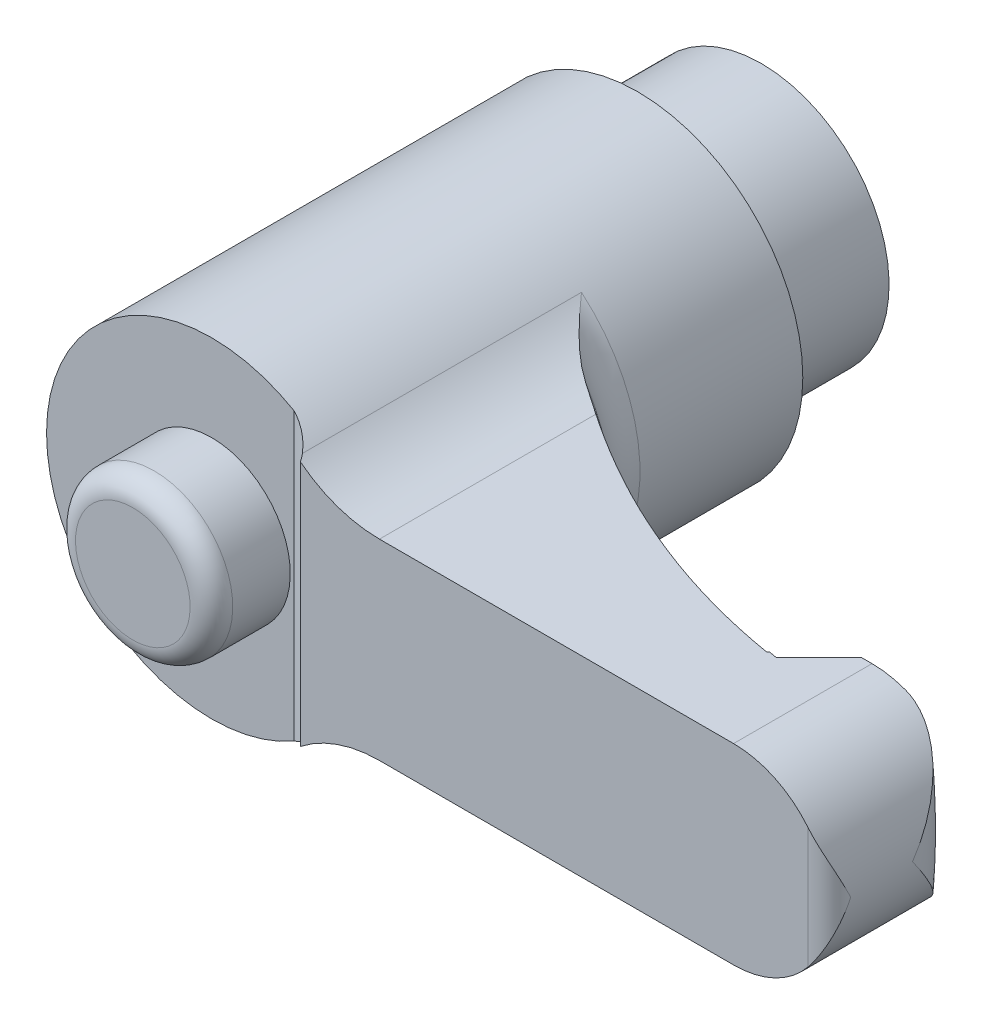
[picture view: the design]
ISO-10303-21;
HEADER;
FILE_DESCRIPTION(('STEP AP214'),'2;1');
FILE_NAME('part.step','',(''),(''),'','','');
FILE_SCHEMA(('AUTOMOTIVE_DESIGN { 1 0 10303 214 1 1 1 1 }'));
ENDSEC;
DATA;
#1=APPLICATION_CONTEXT('core data for automotive mechanical design processes');
#2=APPLICATION_PROTOCOL_DEFINITION('international standard','automotive_design',2000,#1);
#3=PRODUCT_CONTEXT('',#1,'mechanical');
#4=PRODUCT('Part','Part','',(#3));
#5=PRODUCT_RELATED_PRODUCT_CATEGORY('part','',(#4));
#6=PRODUCT_DEFINITION_FORMATION('','',#4);
#7=PRODUCT_DEFINITION_CONTEXT('part definition',#1,'design');
#8=PRODUCT_DEFINITION('design','',#6,#7);
#9=PRODUCT_DEFINITION_SHAPE('','',#8);
#10=(LENGTH_UNIT() NAMED_UNIT(*) SI_UNIT(.MILLI.,.METRE.));
#11=(NAMED_UNIT(*) PLANE_ANGLE_UNIT() SI_UNIT($,.RADIAN.));
#12=(NAMED_UNIT(*) SI_UNIT($,.STERADIAN.) SOLID_ANGLE_UNIT());
#13=UNCERTAINTY_MEASURE_WITH_UNIT(LENGTH_MEASURE(1.E-05),#10,'distance_accuracy_value','');
#14=(GEOMETRIC_REPRESENTATION_CONTEXT(3) GLOBAL_UNCERTAINTY_ASSIGNED_CONTEXT((#13)) GLOBAL_UNIT_ASSIGNED_CONTEXT((#10,
#11,#12)) REPRESENTATION_CONTEXT('',''));
#15=CARTESIAN_POINT('',(0.,0.,0.));
#16=DIRECTION('',(0.,0.,1.));
#17=DIRECTION('',(1.,0.,0.));
#18=AXIS2_PLACEMENT_3D('',#15,#16,#17);
#19=CARTESIAN_POINT('',(0.,0.,10.));
#20=DIRECTION('',(0.,0.,-1.));
#21=DIRECTION('',(-1.,0.,0.));
#22=AXIS2_PLACEMENT_3D('',#19,#20,#21);
#23=PLANE('',#22);
#24=CARTESIAN_POINT('',(0.,0.,10.));
#25=DIRECTION('',(0.,0.,-1.));
#26=DIRECTION('',(-1.,0.,0.));
#27=AXIS2_PLACEMENT_3D('',#24,#25,#26);
#28=CIRCLE('',#27,2.5);
#29=CARTESIAN_POINT('',(-2.5,0.,10.));
#30=VERTEX_POINT('',#29);
#31=EDGE_CURVE('E706',#30,#30,#28,.T.);
#32=ORIENTED_EDGE('',*,*,#31,.T.);
#33=EDGE_LOOP('',(#32));
#34=FACE_BOUND('',#33,.T.);
#35=ADVANCED_FACE('F14',(#34),#23,.T.);
#36=CARTESIAN_POINT('',(4.8,0.,0.));
#37=DIRECTION('',(0.,0.,1.));
#38=DIRECTION('',(0.,-1.,0.));
#39=AXIS2_PLACEMENT_3D('',#36,#37,#38);
#40=PLANE('',#39);
#41=CARTESIAN_POINT('',(0.,0.,0.));
#42=DIRECTION('',(0.,0.,-1.));
#43=DIRECTION('',(0.,1.,0.));
#44=AXIS2_PLACEMENT_3D('',#41,#42,#43);
#45=CIRCLE('',#44,2.5);
#46=CARTESIAN_POINT('',(0.,2.5,0.));
#47=VERTEX_POINT('',#46);
#48=EDGE_CURVE('E373',#47,#47,#45,.T.);
#49=ORIENTED_EDGE('',*,*,#48,.F.);
#50=EDGE_LOOP('',(#49));
#51=FACE_BOUND('',#50,.T.);
#52=CARTESIAN_POINT('',(0.,0.,0.));
#53=DIRECTION('',(0.,0.,-1.));
#54=DIRECTION('',(0.,1.,0.));
#55=AXIS2_PLACEMENT_3D('',#52,#53,#54);
#56=CIRCLE('',#55,4.8);
#57=CARTESIAN_POINT('',(0.,4.8,0.));
#58=VERTEX_POINT('',#57);
#59=EDGE_CURVE('E441',#58,#58,#56,.T.);
#60=ORIENTED_EDGE('',*,*,#59,.T.);
#61=EDGE_LOOP('',(#60));
#62=FACE_BOUND('',#61,.T.);
#63=ADVANCED_FACE('F334',(#51,#62),#40,.F.);
#64=CARTESIAN_POINT('',(0.,0.,26.));
#65=DIRECTION('',(0.,0.,-1.));
#66=DIRECTION('',(0.,1.,0.));
#67=AXIS2_PLACEMENT_3D('',#64,#65,#66);
#68=PLANE('',#67);
#69=CARTESIAN_POINT('',(0.,0.,26.));
#70=DIRECTION('',(0.,0.,-1.));
#71=DIRECTION('',(0.,1.,0.));
#72=AXIS2_PLACEMENT_3D('',#69,#70,#71);
#73=CIRCLE('',#72,7.75);
#74=CARTESIAN_POINT('',(3.875,-6.7116968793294,26.));
#75=VERTEX_POINT('',#74);
#76=CARTESIAN_POINT('',(3.875,6.7116968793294,26.));
#77=VERTEX_POINT('',#76);
#78=EDGE_CURVE('E426',#75,#77,#73,.T.);
#79=ORIENTED_EDGE('',*,*,#78,.F.);
#80=DIRECTION('',(0.,1.,0.));
#81=VECTOR('',#80,1.);
#82=CARTESIAN_POINT('',(3.875,-9.,26.));
#83=LINE('',#82,#81);
#84=EDGE_CURVE('E404',#75,#77,#83,.T.);
#85=ORIENTED_EDGE('',*,*,#84,.T.);
#86=EDGE_LOOP('',(#79,#85));
#87=FACE_BOUND('',#86,.T.);
#88=CARTESIAN_POINT('',(0.,0.,26.));
#89=DIRECTION('',(0.,0.,-1.));
#90=DIRECTION('',(0.,1.,0.));
#91=AXIS2_PLACEMENT_3D('',#88,#89,#90);
#92=CIRCLE('',#91,3.69047619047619);
#93=CARTESIAN_POINT('',(0.,3.69047619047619,26.));
#94=VERTEX_POINT('',#93);
#95=EDGE_CURVE('E9',#94,#94,#92,.F.);
#96=ORIENTED_EDGE('',*,*,#95,.F.);
#97=EDGE_LOOP('',(#96));
#98=FACE_BOUND('',#97,.T.);
#99=ADVANCED_FACE('F16',(#87,#98),#68,.F.);
#100=CARTESIAN_POINT('',(25.5,0.,0.));
#101=DIRECTION('',(0.,0.,1.));
#102=DIRECTION('',(0.,-1.,0.));
#103=AXIS2_PLACEMENT_3D('',#100,#101,#102);
#104=CYLINDRICAL_SURFACE('',#103,4.5);
#105=CARTESIAN_POINT('',(30.,0.,23.1));
#106=CARTESIAN_POINT('',(30.0000000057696,-0.00397224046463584,23.0972162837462));
#107=CARTESIAN_POINT('',(29.9999947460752,-0.00794462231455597,23.0944324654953));
#108=CARTESIAN_POINT('',(29.9991779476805,-0.316207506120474,22.8784039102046));
#109=CARTESIAN_POINT('',(29.967472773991,-0.621260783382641,22.6646232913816));
#110=CARTESIAN_POINT('',(29.8729566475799,-1.07288244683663,22.3499400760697));
#111=CARTESIAN_POINT('',(29.8335087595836,-1.2227001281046,22.2458576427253));
#112=CARTESIAN_POINT('',(29.7386099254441,-1.51933949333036,22.0407893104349));
#113=CARTESIAN_POINT('',(29.6831664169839,-1.6661625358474,21.9398019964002));
#114=CARTESIAN_POINT('',(29.5225221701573,-2.0316181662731,21.690355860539));
#115=CARTESIAN_POINT('',(29.4064726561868,-2.24755940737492,21.5447545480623));
#116=CARTESIAN_POINT('',(29.1349908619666,-2.66429651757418,21.2699985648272));
#117=CARTESIAN_POINT('',(28.9796468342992,-2.86512503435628,21.1408080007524));
#118=CARTESIAN_POINT('',(28.6740094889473,-3.19567948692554,20.9378778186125));
#119=CARTESIAN_POINT('',(28.5328529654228,-3.3303385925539,20.8584463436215));
#120=CARTESIAN_POINT('',(28.2285136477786,-3.58389708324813,20.7186599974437));
#121=CARTESIAN_POINT('',(28.0653563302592,-3.70281438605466,20.6582833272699));
#122=CARTESIAN_POINT('',(27.7569268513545,-3.89637158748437,20.5739705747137));
#123=CARTESIAN_POINT('',(27.6155988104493,-3.97499958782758,20.5449430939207));
#124=CARTESIAN_POINT('',(27.3962983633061,-4.08175109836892,20.516319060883));
#125=CARTESIAN_POINT('',(27.3219652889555,-4.11547521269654,20.5092639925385));
#126=CARTESIAN_POINT('',(27.1713145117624,-4.17892025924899,20.5006475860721));
#127=CARTESIAN_POINT('',(27.0949977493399,-4.20864304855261,20.4990836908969));
#128=CARTESIAN_POINT('',(26.940135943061,-4.26413478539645,20.5019689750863));
#129=CARTESIAN_POINT('',(26.8615759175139,-4.28985895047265,20.5064814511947));
#130=CARTESIAN_POINT('',(26.7037978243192,-4.33677756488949,20.5220962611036));
#131=CARTESIAN_POINT('',(26.624580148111,-4.35797453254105,20.5331949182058));
#132=CARTESIAN_POINT('',(26.4663684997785,-4.39576374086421,20.5623470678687));
#133=CARTESIAN_POINT('',(26.3873744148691,-4.41235899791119,20.5803959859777));
#134=CARTESIAN_POINT('',(26.230581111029,-4.44101436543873,20.6236628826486));
#135=CARTESIAN_POINT('',(26.1527814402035,-4.4530762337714,20.6488780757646));
#136=CARTESIAN_POINT('',(25.9747863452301,-4.47604389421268,20.7158088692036));
#137=CARTESIAN_POINT('',(25.8753706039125,-4.48535121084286,20.7602222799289));
#138=CARTESIAN_POINT('',(25.7308199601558,-4.4943380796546,20.836059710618));
#139=CARTESIAN_POINT('',(25.6833620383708,-4.49650441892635,20.8629005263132));
#140=CARTESIAN_POINT('',(25.5902043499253,-4.4993369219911,20.9195771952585));
#141=CARTESIAN_POINT('',(25.5445050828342,-4.50000266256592,20.9494138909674));
#142=CARTESIAN_POINT('',(25.4998,-4.49999999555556,20.980704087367));
#143=B_SPLINE_CURVE_WITH_KNOTS('',3,(#105,#106,#107,#108,#109,#110,#111,#112,#113,#114,#115,
#116,#117,#118,#119,#120,#121,#122,#123,#124,#125,#126,#127,#128,#129,#130,#131,#132,#133,#134,
#135,#136,#137,#138,#139,#140,#141,#142),.UNSPECIFIED.,.F.,.F.,(4,2,2,2,2,2,2,2,2,2,2,2,2,2,2,2,
2,2,4),(0.,0.0145521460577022,1.12923174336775,1.68863416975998,2.24777690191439,
3.0999476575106,3.95022123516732,4.58000022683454,5.20905610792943,5.69992949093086,
5.94545977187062,6.19087570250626,6.43886797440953,6.68672193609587,6.93441304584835,
7.18200801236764,7.50864895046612,7.67223429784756,7.83586577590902),.UNSPECIFIED.);
#144=CARTESIAN_POINT('',(27.0737254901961,-4.21584962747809,20.5));
#145=VERTEX_POINT('',#144);
#146=CARTESIAN_POINT('',(30.,0.,23.1));
#147=VERTEX_POINT('',#146);
#148=EDGE_CURVE('E133',#145,#147,#143,.F.);
#149=ORIENTED_EDGE('',*,*,#148,.T.);
#150=CARTESIAN_POINT('',(30.,0.,23.1));
#151=CARTESIAN_POINT('',(30.0000000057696,0.00397224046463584,23.0972162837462));
#152=CARTESIAN_POINT('',(29.9999947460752,0.00794462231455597,23.0944324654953));
#153=CARTESIAN_POINT('',(29.9991779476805,0.316207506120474,22.8784039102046));
#154=CARTESIAN_POINT('',(29.967472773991,0.621260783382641,22.6646232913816));
#155=CARTESIAN_POINT('',(29.8729566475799,1.07288244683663,22.3499400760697));
#156=CARTESIAN_POINT('',(29.8335087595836,1.2227001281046,22.2458576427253));
#157=CARTESIAN_POINT('',(29.7386099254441,1.51933949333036,22.0407893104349));
#158=CARTESIAN_POINT('',(29.6831664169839,1.6661625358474,21.9398019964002));
#159=CARTESIAN_POINT('',(29.5225221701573,2.0316181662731,21.690355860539));
#160=CARTESIAN_POINT('',(29.4064726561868,2.24755940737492,21.5447545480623));
#161=CARTESIAN_POINT('',(29.1349908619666,2.66429651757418,21.2699985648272));
#162=CARTESIAN_POINT('',(28.9796468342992,2.86512503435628,21.1408080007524));
#163=CARTESIAN_POINT('',(28.6740094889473,3.19567948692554,20.9378778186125));
#164=CARTESIAN_POINT('',(28.5328529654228,3.3303385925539,20.8584463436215));
#165=CARTESIAN_POINT('',(28.2285136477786,3.58389708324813,20.7186599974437));
#166=CARTESIAN_POINT('',(28.0653563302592,3.70281438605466,20.6582833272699));
#167=CARTESIAN_POINT('',(27.7569268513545,3.89637158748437,20.5739705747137));
#168=CARTESIAN_POINT('',(27.6155988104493,3.97499958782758,20.5449430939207));
#169=CARTESIAN_POINT('',(27.3962983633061,4.08175109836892,20.516319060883));
#170=CARTESIAN_POINT('',(27.3219652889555,4.11547521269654,20.5092639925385));
#171=CARTESIAN_POINT('',(27.1713145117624,4.17892025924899,20.5006475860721));
#172=CARTESIAN_POINT('',(27.0949977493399,4.20864304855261,20.4990836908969));
#173=CARTESIAN_POINT('',(26.940135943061,4.26413478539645,20.5019689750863));
#174=CARTESIAN_POINT('',(26.8615759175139,4.28985895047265,20.5064814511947));
#175=CARTESIAN_POINT('',(26.7037978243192,4.33677756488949,20.5220962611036));
#176=CARTESIAN_POINT('',(26.624580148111,4.35797453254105,20.5331949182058));
#177=CARTESIAN_POINT('',(26.4663684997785,4.39576374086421,20.5623470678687));
#178=CARTESIAN_POINT('',(26.3873744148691,4.41235899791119,20.5803959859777));
#179=CARTESIAN_POINT('',(26.230581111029,4.44101436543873,20.6236628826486));
#180=CARTESIAN_POINT('',(26.1527814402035,4.4530762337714,20.6488780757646));
#181=CARTESIAN_POINT('',(25.9747863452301,4.47604389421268,20.7158088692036));
#182=CARTESIAN_POINT('',(25.8753706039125,4.48535121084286,20.7602222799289));
#183=CARTESIAN_POINT('',(25.7308199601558,4.4943380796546,20.836059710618));
#184=CARTESIAN_POINT('',(25.6833620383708,4.49650441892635,20.8629005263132));
#185=CARTESIAN_POINT('',(25.5902043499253,4.4993369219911,20.9195771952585));
#186=CARTESIAN_POINT('',(25.5445050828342,4.50000266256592,20.9494138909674));
#187=CARTESIAN_POINT('',(25.4998,4.49999999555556,20.980704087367));
#188=B_SPLINE_CURVE_WITH_KNOTS('',3,(#150,#151,#152,#153,#154,#155,#156,#157,#158,#159,#160,
#161,#162,#163,#164,#165,#166,#167,#168,#169,#170,#171,#172,#173,#174,#175,#176,#177,#178,#179,
#180,#181,#182,#183,#184,#185,#186,#187),.UNSPECIFIED.,.F.,.F.,(4,2,2,2,2,2,2,2,2,2,2,2,2,2,2,2,
2,2,4),(0.,0.0145521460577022,1.12923174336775,1.68863416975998,2.24777690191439,
3.0999476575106,3.95022123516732,4.58000022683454,5.20905610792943,5.69992949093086,
5.94545977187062,6.19087570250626,6.43886797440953,6.68672193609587,6.93441304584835,
7.18200801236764,7.50864895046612,7.67223429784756,7.83586577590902),.UNSPECIFIED.);
#189=CARTESIAN_POINT('',(27.0737254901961,4.21584962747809,20.5));
#190=VERTEX_POINT('',#189);
#191=EDGE_CURVE('E130',#147,#190,#188,.T.);
#192=ORIENTED_EDGE('',*,*,#191,.T.);
#193=CARTESIAN_POINT('',(25.5,0.,20.5));
#194=DIRECTION('',(0.,0.,-1.));
#195=DIRECTION('',(0.,1.,0.));
#196=AXIS2_PLACEMENT_3D('',#193,#194,#195);
#197=CIRCLE('',#196,4.5);
#198=CARTESIAN_POINT('',(25.5,4.5,20.5));
#199=VERTEX_POINT('',#198);
#200=EDGE_CURVE('E469',#190,#199,#197,.F.);
#201=ORIENTED_EDGE('',*,*,#200,.T.);
#202=DIRECTION('',(0.,0.,1.));
#203=VECTOR('',#202,1.);
#204=CARTESIAN_POINT('',(25.5,4.5,0.));
#205=LINE('',#204,#203);
#206=CARTESIAN_POINT('',(25.5,4.5,27.));
#207=VERTEX_POINT('',#206);
#208=EDGE_CURVE('E448',#199,#207,#205,.T.);
#209=ORIENTED_EDGE('',*,*,#208,.T.);
#210=CARTESIAN_POINT('',(25.5,0.,27.));
#211=DIRECTION('',(0.,0.,1.));
#212=DIRECTION('',(0.,-1.,0.));
#213=AXIS2_PLACEMENT_3D('',#210,#211,#212);
#214=CIRCLE('',#213,4.5);
#215=CARTESIAN_POINT('',(29.,2.82842712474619,27.));
#216=VERTEX_POINT('',#215);
#217=EDGE_CURVE('E422',#216,#207,#214,.T.);
#218=ORIENTED_EDGE('',*,*,#217,.F.);
#219=CARTESIAN_POINT('',(29.,2.82842712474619,27.));
#220=CARTESIAN_POINT('',(29.0452569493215,2.77244060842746,26.9999705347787));
#221=CARTESIAN_POINT('',(29.08910814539,2.71541373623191,26.9969310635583));
#222=CARTESIAN_POINT('',(29.1737346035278,2.59976408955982,26.9857221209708));
#223=CARTESIAN_POINT('',(29.2145155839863,2.54114457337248,26.9775624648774));
#224=CARTESIAN_POINT('',(29.2926216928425,2.42301598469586,26.9570723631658));
#225=CARTESIAN_POINT('',(29.3299701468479,2.36351669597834,26.9447732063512));
#226=CARTESIAN_POINT('',(29.4015263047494,2.24343051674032,26.9166544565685));
#227=CARTESIAN_POINT('',(29.4357319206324,2.18284293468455,26.9008325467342));
#228=CARTESIAN_POINT('',(29.5205149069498,2.0242761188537,26.8558925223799));
#229=CARTESIAN_POINT('',(29.5686353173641,1.92562477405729,26.8244847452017));
#230=CARTESIAN_POINT('',(29.6569408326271,1.7267576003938,26.7560098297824));
#231=CARTESIAN_POINT('',(29.6971228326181,1.62654117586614,26.7189404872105));
#232=CARTESIAN_POINT('',(29.769924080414,1.42454335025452,26.6403878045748));
#233=CARTESIAN_POINT('',(29.8025090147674,1.32275698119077,26.5988856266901));
#234=CARTESIAN_POINT('',(29.8600923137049,1.1184186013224,26.5127603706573));
#235=CARTESIAN_POINT('',(29.8850925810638,1.0158667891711,26.4681380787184));
#236=CARTESIAN_POINT('',(29.9373931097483,0.763467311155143,26.3559210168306));
#237=CARTESIAN_POINT('',(29.9605764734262,0.613303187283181,26.2871011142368));
#238=CARTESIAN_POINT('',(29.9916507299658,0.312779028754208,26.1474204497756));
#239=CARTESIAN_POINT('',(29.999578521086,0.162420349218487,26.0765650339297));
#240=CARTESIAN_POINT('',(29.9999945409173,0.00809034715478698,26.0038138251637));
#241=CARTESIAN_POINT('',(29.999999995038,0.00404514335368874,26.0019068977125));
#242=CARTESIAN_POINT('',(30.,0.,26.));
#243=B_SPLINE_CURVE_WITH_KNOTS('',3,(#219,#220,#221,#222,#223,#224,#225,#226,#227,#228,#229,
#230,#231,#232,#233,#234,#235,#236,#237,#238,#239,#240,#241,#242),.UNSPECIFIED.,.F.,.F.,(4,2,2,
2,2,2,2,2,2,2,2,4),(0.,0.215782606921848,0.431152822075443,0.644930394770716,0.858848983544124,
1.20082332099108,1.5429311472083,1.88655545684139,2.23009348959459,2.7297347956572,
3.22816610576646,3.2415825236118),.UNSPECIFIED.);
#244=CARTESIAN_POINT('',(30.,0.,26.));
#245=VERTEX_POINT('',#244);
#246=EDGE_CURVE('E173',#245,#216,#243,.F.);
#247=ORIENTED_EDGE('',*,*,#246,.F.);
#248=CARTESIAN_POINT('',(29.,-2.82842712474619,27.));
#249=CARTESIAN_POINT('',(29.0452569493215,-2.77244060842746,26.9999705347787));
#250=CARTESIAN_POINT('',(29.08910814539,-2.71541373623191,26.9969310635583));
#251=CARTESIAN_POINT('',(29.1737346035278,-2.59976408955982,26.9857221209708));
#252=CARTESIAN_POINT('',(29.2145155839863,-2.54114457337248,26.9775624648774));
#253=CARTESIAN_POINT('',(29.2926216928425,-2.42301598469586,26.9570723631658));
#254=CARTESIAN_POINT('',(29.3299701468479,-2.36351669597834,26.9447732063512));
#255=CARTESIAN_POINT('',(29.4015263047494,-2.24343051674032,26.9166544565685));
#256=CARTESIAN_POINT('',(29.4357319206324,-2.18284293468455,26.9008325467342));
#257=CARTESIAN_POINT('',(29.5205149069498,-2.0242761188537,26.8558925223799));
#258=CARTESIAN_POINT('',(29.5686353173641,-1.92562477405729,26.8244847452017));
#259=CARTESIAN_POINT('',(29.6569408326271,-1.7267576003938,26.7560098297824));
#260=CARTESIAN_POINT('',(29.6971228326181,-1.62654117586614,26.7189404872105));
#261=CARTESIAN_POINT('',(29.769924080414,-1.42454335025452,26.6403878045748));
#262=CARTESIAN_POINT('',(29.8025090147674,-1.32275698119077,26.5988856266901));
#263=CARTESIAN_POINT('',(29.8600923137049,-1.1184186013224,26.5127603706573));
#264=CARTESIAN_POINT('',(29.8850925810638,-1.0158667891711,26.4681380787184));
#265=CARTESIAN_POINT('',(29.9373931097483,-0.763467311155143,26.3559210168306));
#266=CARTESIAN_POINT('',(29.9605764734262,-0.613303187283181,26.2871011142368));
#267=CARTESIAN_POINT('',(29.9916507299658,-0.312779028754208,26.1474204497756));
#268=CARTESIAN_POINT('',(29.999578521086,-0.162420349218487,26.0765650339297));
#269=CARTESIAN_POINT('',(29.9999945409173,-0.00809034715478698,26.0038138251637));
#270=CARTESIAN_POINT('',(29.999999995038,-0.00404514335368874,26.0019068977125));
#271=CARTESIAN_POINT('',(30.,0.,26.));
#272=B_SPLINE_CURVE_WITH_KNOTS('',3,(#248,#249,#250,#251,#252,#253,#254,#255,#256,#257,#258,
#259,#260,#261,#262,#263,#264,#265,#266,#267,#268,#269,#270,#271),.UNSPECIFIED.,.F.,.F.,(4,2,2,
2,2,2,2,2,2,2,2,4),(0.,0.215782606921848,0.431152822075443,0.644930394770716,0.858848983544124,
1.20082332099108,1.5429311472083,1.88655545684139,2.23009348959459,2.7297347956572,
3.22816610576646,3.2415825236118),.UNSPECIFIED.);
#273=CARTESIAN_POINT('',(29.,-2.82842712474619,27.));
#274=VERTEX_POINT('',#273);
#275=EDGE_CURVE('E22',#274,#245,#272,.T.);
#276=ORIENTED_EDGE('',*,*,#275,.F.);
#277=CARTESIAN_POINT('',(25.5,-4.5,27.));
#278=VERTEX_POINT('',#277);
#279=EDGE_CURVE('E419',#278,#274,#214,.T.);
#280=ORIENTED_EDGE('',*,*,#279,.F.);
#281=DIRECTION('',(0.,0.,1.));
#282=VECTOR('',#281,1.);
#283=CARTESIAN_POINT('',(25.5,-4.5,0.));
#284=LINE('',#283,#282);
#285=CARTESIAN_POINT('',(25.5,-4.5,20.5));
#286=VERTEX_POINT('',#285);
#287=EDGE_CURVE('E451',#286,#278,#284,.T.);
#288=ORIENTED_EDGE('',*,*,#287,.F.);
#289=EDGE_CURVE('E140',#286,#145,#197,.F.);
#290=ORIENTED_EDGE('',*,*,#289,.T.);
#291=EDGE_LOOP('',(#149,#192,#201,#209,#218,#247,#276,#280,#288,#290));
#292=FACE_BOUND('',#291,.T.);
#293=ADVANCED_FACE('F138',(#292),#104,.T.);
#294=CARTESIAN_POINT('',(28.072410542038,-9.,-7.06806810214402));
#295=DIRECTION('',(0.,1.,0.));
#296=DIRECTION('',(-1.,0.,0.));
#297=AXIS2_PLACEMENT_3D('',#294,#295,#296);
#298=CYLINDRICAL_SURFACE('',#297,30.);
#299=CARTESIAN_POINT('',(22.457864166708,5.40076351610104,22.4018635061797));
#300=CARTESIAN_POINT('',(22.5328704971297,5.02783315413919,22.4161416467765));
#301=CARTESIAN_POINT('',(22.6003478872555,4.65331694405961,22.4287120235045));
#302=CARTESIAN_POINT('',(22.7199001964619,3.90172149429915,22.4506465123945));
#303=CARTESIAN_POINT('',(22.7719742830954,3.52464211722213,22.4600104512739));
#304=CARTESIAN_POINT('',(22.860391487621,2.76836181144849,22.4757441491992));
#305=CARTESIAN_POINT('',(22.8967259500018,2.38915983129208,22.4821122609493));
#306=CARTESIAN_POINT('',(22.953399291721,1.62955869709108,22.4919810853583));
#307=CARTESIAN_POINT('',(22.9737386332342,1.24915957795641,22.4954818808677));
#308=CARTESIAN_POINT('',(23.0101209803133,0.119914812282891,22.5017516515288));
#309=CARTESIAN_POINT('',(23.0030278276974,-0.62982701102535,22.5005458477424));
#310=CARTESIAN_POINT('',(22.9265280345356,-2.12549757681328,22.487326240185));
#311=CARTESIAN_POINT('',(22.8571649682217,-2.87142861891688,22.4753199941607));
#312=CARTESIAN_POINT('',(22.717445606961,-3.91200869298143,22.450161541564));
#313=CARTESIAN_POINT('',(22.6723784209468,-4.21035002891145,22.4419679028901));
#314=CARTESIAN_POINT('',(22.5724363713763,-4.80637536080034,22.4235048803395));
#315=CARTESIAN_POINT('',(22.5175283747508,-5.10405358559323,22.4132284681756));
#316=CARTESIAN_POINT('',(22.457864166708,-5.40076351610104,22.4018635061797));
#317=B_SPLINE_CURVE_WITH_KNOTS('',3,(#299,#300,#301,#302,#303,#304,#305,#306,#307,#308,#309,
#310,#311,#312,#313,#314,#315,#316),.UNSPECIFIED.,.F.,.F.,(4,2,2,2,2,2,2,2,4),(0.,
1.14192528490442,2.28391227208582,3.4265264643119,4.56910763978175,6.81558260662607,
9.06048679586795,9.96586555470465,10.8743519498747),.UNSPECIFIED.);
#318=CARTESIAN_POINT('',(23.,0.,22.5));
#319=VERTEX_POINT('',#318);
#320=CARTESIAN_POINT('',(22.6238084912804,-4.5,22.4329951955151));
#321=VERTEX_POINT('',#320);
#322=EDGE_CURVE('E136',#319,#321,#317,.T.);
#323=ORIENTED_EDGE('',*,*,#322,.F.);
#324=DIRECTION('',(0.,1.,0.));
#325=VECTOR('',#324,1.);
#326=CARTESIAN_POINT('',(23.,-9.,22.5));
#327=LINE('',#326,#325);
#328=CARTESIAN_POINT('',(23.,-4.5,22.5));
#329=VERTEX_POINT('',#328);
#330=EDGE_CURVE('E386',#329,#319,#327,.T.);
#331=ORIENTED_EDGE('',*,*,#330,.F.);
#332=CARTESIAN_POINT('',(28.072410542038,-4.5,-7.06806810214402));
#333=DIRECTION('',(0.,1.,0.));
#334=DIRECTION('',(-1.,0.,0.));
#335=AXIS2_PLACEMENT_3D('',#332,#333,#334);
#336=CIRCLE('',#335,30.);
#337=EDGE_CURVE('E388',#329,#321,#336,.F.);
#338=ORIENTED_EDGE('',*,*,#337,.T.);
#339=EDGE_LOOP('',(#323,#331,#338));
#340=FACE_BOUND('',#339,.T.);
#341=ADVANCED_FACE('F162',(#340),#298,.F.);
#342=CARTESIAN_POINT('',(27.4,-9.,20.5));
#343=DIRECTION('',(0.,0.,-1.));
#344=DIRECTION('',(0.,1.,0.));
#345=AXIS2_PLACEMENT_3D('',#342,#343,#344);
#346=PLANE('',#345);
#347=ORIENTED_EDGE('',*,*,#200,.F.);
#348=CARTESIAN_POINT('',(0.,0.,20.5));
#349=DIRECTION('',(0.,0.,-1.));
#350=DIRECTION('',(0.,1.,0.));
#351=AXIS2_PLACEMENT_3D('',#348,#349,#350);
#352=CIRCLE('',#351,27.4);
#353=EDGE_CURVE('E37',#190,#145,#352,.T.);
#354=ORIENTED_EDGE('',*,*,#353,.T.);
#355=ORIENTED_EDGE('',*,*,#289,.F.);
#356=DIRECTION('',(-1.,0.,0.));
#357=VECTOR('',#356,1.);
#358=CARTESIAN_POINT('',(25.5,-4.5,20.5));
#359=LINE('',#358,#357);
#360=CARTESIAN_POINT('',(25.,-4.5,20.5));
#361=VERTEX_POINT('',#360);
#362=EDGE_CURVE('E420',#286,#361,#359,.T.);
#363=ORIENTED_EDGE('',*,*,#362,.T.);
#364=DIRECTION('',(0.,1.,0.));
#365=VECTOR('',#364,1.);
#366=CARTESIAN_POINT('',(25.,-9.,20.5));
#367=LINE('',#366,#365);
#368=CARTESIAN_POINT('',(25.,4.5,20.5));
#369=VERTEX_POINT('',#368);
#370=EDGE_CURVE('E396',#361,#369,#367,.T.);
#371=ORIENTED_EDGE('',*,*,#370,.T.);
#372=DIRECTION('',(1.,0.,0.));
#373=VECTOR('',#372,1.);
#374=CARTESIAN_POINT('',(8.87764045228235,4.5,20.5));
#375=LINE('',#374,#373);
#376=EDGE_CURVE('E466',#369,#199,#375,.T.);
#377=ORIENTED_EDGE('',*,*,#376,.T.);
#378=EDGE_LOOP('',(#347,#354,#355,#363,#371,#377));
#379=FACE_BOUND('',#378,.T.);
#380=ADVANCED_FACE('F191',(#379),#346,.T.);
#381=CARTESIAN_POINT('',(0.,0.,27.));
#382=DIRECTION('',(0.,0.,1.));
#383=DIRECTION('',(0.,-1.,0.));
#384=AXIS2_PLACEMENT_3D('',#381,#382,#383);
#385=PLANE('',#384);
#386=CARTESIAN_POINT('',(8.87764045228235,10.5,27.));
#387=DIRECTION('',(0.,0.,1.));
#388=DIRECTION('',(1.,0.,0.));
#389=AXIS2_PLACEMENT_3D('',#386,#387,#388);
#390=CIRCLE('',#389,6.);
#391=CARTESIAN_POINT('',(5.16666666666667,5.78527057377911,27.));
#392=VERTEX_POINT('',#391);
#393=CARTESIAN_POINT('',(8.87764045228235,4.5,27.));
#394=VERTEX_POINT('',#393);
#395=EDGE_CURVE('E463',#392,#394,#390,.T.);
#396=ORIENTED_EDGE('',*,*,#395,.F.);
#397=DIRECTION('',(0.,1.,0.));
#398=VECTOR('',#397,1.);
#399=CARTESIAN_POINT('',(5.16666666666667,-9.,27.));
#400=LINE('',#399,#398);
#401=CARTESIAN_POINT('',(5.16666666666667,-5.78527057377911,27.));
#402=VERTEX_POINT('',#401);
#403=EDGE_CURVE('E402',#402,#392,#400,.T.);
#404=ORIENTED_EDGE('',*,*,#403,.F.);
#405=CARTESIAN_POINT('',(8.87764045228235,-10.5,27.));
#406=DIRECTION('',(0.,0.,1.));
#407=DIRECTION('',(1.,0.,0.));
#408=AXIS2_PLACEMENT_3D('',#405,#406,#407);
#409=CIRCLE('',#408,6.);
#410=CARTESIAN_POINT('',(8.87764045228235,-4.5,27.));
#411=VERTEX_POINT('',#410);
#412=EDGE_CURVE('E418',#411,#402,#409,.T.);
#413=ORIENTED_EDGE('',*,*,#412,.F.);
#414=DIRECTION('',(-1.,0.,0.));
#415=VECTOR('',#414,1.);
#416=CARTESIAN_POINT('',(25.5,-4.5,27.));
#417=LINE('',#416,#415);
#418=EDGE_CURVE('E457',#278,#411,#417,.T.);
#419=ORIENTED_EDGE('',*,*,#418,.F.);
#420=ORIENTED_EDGE('',*,*,#279,.T.);
#421=DIRECTION('',(0.,1.,0.));
#422=VECTOR('',#421,1.);
#423=CARTESIAN_POINT('',(29.,-9.,27.));
#424=LINE('',#423,#422);
#425=EDGE_CURVE('E397',#274,#216,#424,.T.);
#426=ORIENTED_EDGE('',*,*,#425,.T.);
#427=ORIENTED_EDGE('',*,*,#217,.T.);
#428=DIRECTION('',(1.,0.,0.));
#429=VECTOR('',#428,1.);
#430=CARTESIAN_POINT('',(8.87764045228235,4.5,27.));
#431=LINE('',#430,#429);
#432=EDGE_CURVE('E460',#394,#207,#431,.T.);
#433=ORIENTED_EDGE('',*,*,#432,.F.);
#434=EDGE_LOOP('',(#396,#404,#413,#419,#420,#426,#427,#433));
#435=FACE_BOUND('',#434,.T.);
#436=ADVANCED_FACE('F238',(#435),#385,.T.);
#437=CARTESIAN_POINT('',(0.,0.,0.));
#438=DIRECTION('',(0.,0.,-1.));
#439=DIRECTION('',(0.,1.,0.));
#440=AXIS2_PLACEMENT_3D('',#437,#438,#439);
#441=CYLINDRICAL_SURFACE('',#440,7.75);
#442=CARTESIAN_POINT('',(0.,0.,13.6426560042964));
#443=DIRECTION('',(0.,0.,-1.));
#444=DIRECTION('',(0.,1.,0.));
#445=AXIS2_PLACEMENT_3D('',#442,#443,#444);
#446=CIRCLE('',#445,7.75);
#447=CARTESIAN_POINT('',(5.00376098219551,5.91818181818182,13.6426560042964));
#448=VERTEX_POINT('',#447);
#449=CARTESIAN_POINT('',(5.00376098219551,-5.91818181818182,13.6426560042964));
#450=VERTEX_POINT('',#449);
#451=EDGE_CURVE('E367',#448,#450,#446,.T.);
#452=ORIENTED_EDGE('',*,*,#451,.T.);
#453=DIRECTION('',(0.,0.,1.));
#454=VECTOR('',#453,1.);
#455=CARTESIAN_POINT('',(5.00376098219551,-5.91818181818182,0.));
#456=LINE('',#455,#454);
#457=CARTESIAN_POINT('',(5.00376098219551,-5.91818181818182,26.7442638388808));
#458=VERTEX_POINT('',#457);
#459=EDGE_CURVE('E416',#450,#458,#456,.T.);
#460=ORIENTED_EDGE('',*,*,#459,.T.);
#461=CARTESIAN_POINT('',(3.875,-6.7116968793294,26.));
#462=CARTESIAN_POINT('',(3.9487248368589,-6.66914880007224,26.0179048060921));
#463=CARTESIAN_POINT('',(4.02097408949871,-6.62579988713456,26.039874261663));
#464=CARTESIAN_POINT('',(4.16199829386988,-6.53812669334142,26.0915573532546));
#465=CARTESIAN_POINT('',(4.23077434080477,-6.49380272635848,26.1212685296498));
#466=CARTESIAN_POINT('',(4.36202505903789,-6.40634475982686,26.1868862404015));
#467=CARTESIAN_POINT('',(4.42463632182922,-6.36322379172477,26.2225378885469));
#468=CARTESIAN_POINT('',(4.54579687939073,-6.27724013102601,26.3004737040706));
#469=CARTESIAN_POINT('',(4.60434578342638,-6.23437746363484,26.3427585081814));
#470=CARTESIAN_POINT('',(4.71026264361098,-6.1546555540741,26.4283893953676));
#471=CARTESIAN_POINT('',(4.75813291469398,-6.11768751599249,26.4710140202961));
#472=CARTESIAN_POINT('',(4.8500303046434,-6.04509175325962,26.56120031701));
#473=CARTESIAN_POINT('',(4.89405965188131,-6.00946325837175,26.6087590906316));
#474=CARTESIAN_POINT('',(4.97925799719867,-5.9390764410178,26.7103994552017));
#475=CARTESIAN_POINT('',(5.02029084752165,-5.90438218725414,26.7646407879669));
#476=CARTESIAN_POINT('',(5.09738332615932,-5.83796295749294,26.8783962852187));
#477=CARTESIAN_POINT('',(5.13343386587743,-5.80624344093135,26.9379197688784));
#478=CARTESIAN_POINT('',(5.16666666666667,-5.77650894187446,27.));
#479=B_SPLINE_CURVE_WITH_KNOTS('',3,(#461,#462,#463,#464,#465,#466,#467,#468,#469,#470,#471,
#472,#473,#474,#475,#476,#477,#478),.UNSPECIFIED.,.F.,.F.,(4,2,2,2,2,2,2,2,4),(0.,
0.260811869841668,0.521540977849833,0.773092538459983,1.02466826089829,1.24638864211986,
1.4679795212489,1.69664297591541,1.92571819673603),.UNSPECIFIED.);
#480=EDGE_CURVE('E213',#75,#458,#479,.T.);
#481=ORIENTED_EDGE('',*,*,#480,.F.);
#482=ORIENTED_EDGE('',*,*,#78,.T.);
#483=CARTESIAN_POINT('',(5.16666666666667,5.77650894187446,27.));
#484=CARTESIAN_POINT('',(5.13714077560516,5.80292379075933,26.9448365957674));
#485=CARTESIAN_POINT('',(5.1053831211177,5.83091583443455,26.8916890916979));
#486=CARTESIAN_POINT('',(5.03785941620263,5.88934998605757,26.7895453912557));
#487=CARTESIAN_POINT('',(5.00209830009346,5.91978906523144,26.7405442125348));
#488=CARTESIAN_POINT('',(4.92700880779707,5.98243056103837,26.646752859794));
#489=CARTESIAN_POINT('',(4.88768622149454,6.01463008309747,26.6019560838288));
#490=CARTESIAN_POINT('',(4.80573825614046,6.08030777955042,26.5165060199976));
#491=CARTESIAN_POINT('',(4.76311181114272,6.11378636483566,26.4758540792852));
#492=CARTESIAN_POINT('',(4.63114473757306,6.21507952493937,26.3605779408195));
#493=CARTESIAN_POINT('',(4.53728284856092,6.28411879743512,26.2920994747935));
#494=CARTESIAN_POINT('',(4.3393749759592,6.42237347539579,26.1724069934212));
#495=CARTESIAN_POINT('',(4.23533663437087,6.49158871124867,26.1211801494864));
#496=CARTESIAN_POINT('',(4.08621326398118,6.5854168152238,26.0632790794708));
#497=CARTESIAN_POINT('',(4.04469277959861,6.61100425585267,26.0487072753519));
#498=CARTESIAN_POINT('',(3.96061680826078,6.66171281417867,26.0222973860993));
#499=CARTESIAN_POINT('',(3.91806319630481,6.68683464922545,26.0104547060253));
#500=CARTESIAN_POINT('',(3.8750000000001,6.7116968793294,26.));
#501=B_SPLINE_CURVE_WITH_KNOTS('',3,(#483,#484,#485,#486,#487,#488,#489,#490,#491,#492,#493,
#494,#495,#496,#497,#498,#499,#500),.UNSPECIFIED.,.F.,.F.,(4,2,2,2,2,2,2,2,4),(0.,
0.203583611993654,0.406919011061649,0.609929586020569,0.813005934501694,1.21684507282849,
1.62038324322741,1.77301957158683,1.9253970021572),.UNSPECIFIED.);
#502=CARTESIAN_POINT('',(5.0037609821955,5.91818181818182,26.7442638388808));
#503=VERTEX_POINT('',#502);
#504=EDGE_CURVE('E226',#503,#77,#501,.T.);
#505=ORIENTED_EDGE('',*,*,#504,.F.);
#506=DIRECTION('',(0.,0.,1.));
#507=VECTOR('',#506,1.);
#508=CARTESIAN_POINT('',(5.00376098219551,5.91818181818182,0.));
#509=LINE('',#508,#507);
#510=EDGE_CURVE('E444',#448,#503,#509,.T.);
#511=ORIENTED_EDGE('',*,*,#510,.F.);
#512=EDGE_LOOP('',(#452,#460,#481,#482,#505,#511));
#513=FACE_BOUND('',#512,.T.);
#514=CARTESIAN_POINT('',(0.,0.,6.));
#515=DIRECTION('',(0.,0.,-1.));
#516=DIRECTION('',(0.,1.,0.));
#517=AXIS2_PLACEMENT_3D('',#514,#515,#516);
#518=CIRCLE('',#517,7.75);
#519=CARTESIAN_POINT('',(0.,7.75,6.));
#520=VERTEX_POINT('',#519);
#521=EDGE_CURVE('E429',#520,#520,#518,.T.);
#522=ORIENTED_EDGE('',*,*,#521,.F.);
#523=EDGE_LOOP('',(#522));
#524=FACE_BOUND('',#523,.T.);
#525=ADVANCED_FACE('F236',(#513,#524),#441,.T.);
#526=CARTESIAN_POINT('',(8.87764045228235,10.5,0.));
#527=DIRECTION('',(0.,0.,1.));
#528=DIRECTION('',(0.,-1.,0.));
#529=AXIS2_PLACEMENT_3D('',#526,#527,#528);
#530=CYLINDRICAL_SURFACE('',#529,6.);
#531=DIRECTION('',(0.,0.,1.));
#532=VECTOR('',#531,1.);
#533=CARTESIAN_POINT('',(8.87764045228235,4.5,0.));
#534=LINE('',#533,#532);
#535=CARTESIAN_POINT('',(8.87764045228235,4.5,16.8419191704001));
#536=VERTEX_POINT('',#535);
#537=EDGE_CURVE('E446',#536,#394,#534,.T.);
#538=ORIENTED_EDGE('',*,*,#537,.F.);
#539=CARTESIAN_POINT('',(8.87784045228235,4.50000000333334,16.8420543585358));
#540=CARTESIAN_POINT('',(8.76298675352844,4.50000678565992,16.7644412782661));
#541=CARTESIAN_POINT('',(8.64795886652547,4.50329006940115,16.687069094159));
#542=CARTESIAN_POINT('',(8.41786670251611,4.51653249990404,16.5336144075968));
#543=CARTESIAN_POINT('',(8.30280331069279,4.52647413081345,16.457529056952));
#544=CARTESIAN_POINT('',(8.07233993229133,4.55315590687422,16.3070362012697));
#545=CARTESIAN_POINT('',(7.95693991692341,4.56989665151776,16.2326288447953));
#546=CARTESIAN_POINT('',(7.72548993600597,4.61048878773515,16.0861329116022));
#547=CARTESIAN_POINT('',(7.60943905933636,4.63435875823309,16.0140509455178));
#548=CARTESIAN_POINT('',(7.49320434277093,4.66190641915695,15.9436475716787));
#549=B_SPLINE_CURVE_WITH_KNOTS('',3,(#539,#540,#541,#542,#543,#544,#545,#546,#547,#548),
.UNSPECIFIED.,.F.,.F.,(4,2,2,2,4),(0.,0.415830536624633,0.830571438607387,1.24534891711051,
1.66121688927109),.UNSPECIFIED.);
#550=CARTESIAN_POINT('',(7.49353468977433,4.66182809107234,15.9438475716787));
#551=VERTEX_POINT('',#550);
#552=EDGE_CURVE('E252',#536,#551,#549,.T.);
#553=ORIENTED_EDGE('',*,*,#552,.T.);
#554=CARTESIAN_POINT('',(7.49386505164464,4.66174977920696,15.9440475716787));
#555=CARTESIAN_POINT('',(7.41534599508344,4.68036361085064,15.8965108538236));
#556=CARTESIAN_POINT('',(7.33813459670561,4.70033346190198,15.8474028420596));
#557=CARTESIAN_POINT('',(7.18628313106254,4.74278447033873,15.7464454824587));
#558=CARTESIAN_POINT('',(7.11164195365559,4.76526452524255,15.694597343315));
#559=CARTESIAN_POINT('',(6.89171782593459,4.83609524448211,15.5357042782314));
#560=CARTESIAN_POINT('',(6.75010221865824,4.88791699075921,15.4251060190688));
#561=CARTESIAN_POINT('',(6.47674906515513,4.99932791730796,15.1976148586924));
#562=CARTESIAN_POINT('',(6.34496293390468,5.05887426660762,15.0807586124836));
#563=CARTESIAN_POINT('',(6.08952700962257,5.18523508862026,14.8421034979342));
#564=CARTESIAN_POINT('',(5.96588083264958,5.25205275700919,14.7203024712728));
#565=CARTESIAN_POINT('',(5.6959472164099,5.41010140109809,14.4425118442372));
#566=CARTESIAN_POINT('',(5.55174299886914,5.50325599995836,14.2855983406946));
#567=CARTESIAN_POINT('',(5.27355500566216,5.70004368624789,13.9693256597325));
#568=CARTESIAN_POINT('',(5.13957057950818,5.80367610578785,13.8099666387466));
#569=CARTESIAN_POINT('',(5.00807252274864,5.91453907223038,13.6479722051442));
#570=CARTESIAN_POINT('',(5.00591610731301,5.91635969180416,13.6453140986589));
#571=CARTESIAN_POINT('',(5.00376098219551,5.91818181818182,13.6426560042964));
#572=B_SPLINE_CURVE_WITH_KNOTS('',3,(#554,#555,#556,#557,#558,#559,#560,#561,#562,#563,#564,
#565,#566,#567,#568,#569,#570,#571),.UNSPECIFIED.,.F.,.F.,(4,2,2,2,2,2,2,2,4),(0.,
0.280888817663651,0.561654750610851,1.12199628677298,1.67935400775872,2.2369576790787,
2.93418472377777,3.63136735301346,3.6429980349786),.UNSPECIFIED.);
#573=EDGE_CURVE('E243',#551,#448,#572,.T.);
#574=ORIENTED_EDGE('',*,*,#573,.T.);
#575=ORIENTED_EDGE('',*,*,#510,.T.);
#576=CARTESIAN_POINT('',(5.16666666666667,5.78527057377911,27.));
#577=CARTESIAN_POINT('',(5.1544362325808,5.79489712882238,26.9771411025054));
#578=CARTESIAN_POINT('',(5.14182657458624,5.80489933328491,26.9546446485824));
#579=CARTESIAN_POINT('',(5.11593353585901,5.82561925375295,26.910451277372));
#580=CARTESIAN_POINT('',(5.10265156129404,5.83633549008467,26.8887528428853));
#581=CARTESIAN_POINT('',(5.07544919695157,5.85848632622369,26.8461383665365));
#582=CARTESIAN_POINT('',(5.06152881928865,5.86992091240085,26.8252223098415));
#583=CARTESIAN_POINT('',(5.03308032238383,5.89351543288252,26.784152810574));
#584=CARTESIAN_POINT('',(5.0185510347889,5.90567678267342,26.7640009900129));
#585=CARTESIAN_POINT('',(5.0037609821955,5.91818181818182,26.7442638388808));
#586=B_SPLINE_CURVE_WITH_KNOTS('',3,(#576,#577,#578,#579,#580,#581,#582,#583,#584,#585),
.UNSPECIFIED.,.F.,.F.,(4,2,2,2,4),(0.,0.0829550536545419,0.165743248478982,0.248529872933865,
0.331483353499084),.UNSPECIFIED.);
#587=EDGE_CURVE('E220',#392,#503,#586,.T.);
#588=ORIENTED_EDGE('',*,*,#587,.F.);
#589=ORIENTED_EDGE('',*,*,#395,.T.);
#590=EDGE_LOOP('',(#538,#553,#574,#575,#588,#589));
#591=FACE_BOUND('',#590,.T.);
#592=ADVANCED_FACE('F232',(#591),#530,.F.);
#593=CARTESIAN_POINT('',(8.87764045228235,4.5,0.));
#594=DIRECTION('',(0.,-1.,0.));
#595=DIRECTION('',(1.,0.,0.));
#596=AXIS2_PLACEMENT_3D('',#593,#594,#595);
#597=PLANE('',#596);
#598=CARTESIAN_POINT('',(28.072410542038,4.5,-7.06806810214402));
#599=DIRECTION('',(0.,-1.,0.));
#600=DIRECTION('',(1.,0.,0.));
#601=AXIS2_PLACEMENT_3D('',#598,#599,#600);
#602=CIRCLE('',#601,30.);
#603=CARTESIAN_POINT('',(22.6238084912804,4.5,22.432995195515));
#604=VERTEX_POINT('',#603);
#605=CARTESIAN_POINT('',(23.,4.5,22.5));
#606=VERTEX_POINT('',#605);
#607=EDGE_CURVE('E391',#604,#606,#602,.F.);
#608=ORIENTED_EDGE('',*,*,#607,.F.);
#609=CARTESIAN_POINT('',(44.3300735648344,4.5,0.942111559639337));
#610=CARTESIAN_POINT('',(43.4547012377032,4.5,1.81300466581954));
#611=CARTESIAN_POINT('',(42.5792011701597,4.5,2.68376940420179));
#612=CARTESIAN_POINT('',(40.8278840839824,4.5,4.42498033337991));
#613=CARTESIAN_POINT('',(39.9520670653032,4.5,5.29542652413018));
#614=CARTESIAN_POINT('',(37.3240501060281,4.5,7.90619283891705));
#615=CARTESIAN_POINT('',(35.5712829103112,4.5,9.64594205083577));
#616=CARTESIAN_POINT('',(32.0635642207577,4.5,13.1230346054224));
#617=CARTESIAN_POINT('',(30.3086128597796,4.5,14.8603780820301));
#618=CARTESIAN_POINT('',(27.6733297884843,4.5,17.4635089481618));
#619=CARTESIAN_POINT('',(26.7944244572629,4.5,18.3307401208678));
#620=CARTESIAN_POINT('',(25.0353323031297,4.5,20.0639019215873));
#621=CARTESIAN_POINT('',(24.155145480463,4.5,20.9298325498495));
#622=CARTESIAN_POINT('',(22.3129521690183,4.5,22.7385304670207));
#623=CARTESIAN_POINT('',(21.3507796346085,4.5,23.6811286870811));
#624=CARTESIAN_POINT('',(19.4234130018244,4.5,25.5632155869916));
#625=CARTESIAN_POINT('',(18.4582189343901,4.5,26.5027042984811));
#626=CARTESIAN_POINT('',(17.0068469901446,4.5,27.9082821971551));
#627=CARTESIAN_POINT('',(16.5224491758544,4.5,28.3762088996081));
#628=CARTESIAN_POINT('',(15.5521170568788,4.5,29.3104634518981));
#629=CARTESIAN_POINT('',(15.0661827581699,4.5,29.7767913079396));
#630=CARTESIAN_POINT('',(14.0922926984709,4.5,30.7073654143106));
#631=CARTESIAN_POINT('',(13.6043368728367,4.5,31.1716115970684));
#632=CARTESIAN_POINT('',(12.8703741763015,4.5,31.8658425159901));
#633=CARTESIAN_POINT('',(12.625380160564,4.5,32.0968979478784));
#634=CARTESIAN_POINT('',(12.1345901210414,4.5,32.5581570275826));
#635=CARTESIAN_POINT('',(11.8887940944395,4.5,32.7883606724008));
#636=CARTESIAN_POINT('',(11.6425345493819,4.5,33.0180686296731));
#637=B_SPLINE_CURVE_WITH_KNOTS('',3,(#609,#610,#611,#612,#613,#614,#615,#616,#617,#618,#619,
#620,#621,#622,#623,#624,#625,#626,#627,#628,#629,#630,#631,#632,#633,#634,#635,#636),
.UNSPECIFIED.,.F.,.F.,(4,2,2,2,2,2,2,2,2,2,2,2,2,4),(0.,3.70440058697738,7.40880170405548,
14.8175982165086,22.225964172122,25.9301609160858,29.6343569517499,33.6751954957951,
37.7159927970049,39.736477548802,41.7569544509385,43.7774964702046,44.7877808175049,
45.7980687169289),.UNSPECIFIED.);
#638=CARTESIAN_POINT('',(22.55548713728,4.5,22.5));
#639=VERTEX_POINT('',#638);
#640=EDGE_CURVE('E298',#604,#639,#637,.T.);
#641=ORIENTED_EDGE('',*,*,#640,.T.);
#642=CARTESIAN_POINT('',(15.4388208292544,4.5,20.4312501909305));
#643=CARTESIAN_POINT('',(14.9382009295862,4.5,20.2216724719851));
#644=CARTESIAN_POINT('',(14.4426076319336,4.5,19.9999912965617));
#645=CARTESIAN_POINT('',(13.4622769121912,4.5,19.5336725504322));
#646=CARTESIAN_POINT('',(12.9775414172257,4.5,19.2890309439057));
#647=CARTESIAN_POINT('',(12.0194633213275,4.5,18.778303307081));
#648=CARTESIAN_POINT('',(11.5461217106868,4.5,18.5122154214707));
#649=CARTESIAN_POINT('',(10.6110367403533,4.5,17.9604954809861));
#650=CARTESIAN_POINT('',(10.1492927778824,4.5,17.6748644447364));
#651=CARTESIAN_POINT('',(9.23133715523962,4.5,17.0827723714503));
#652=CARTESIAN_POINT('',(8.77526312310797,4.5,16.776098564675));
#653=CARTESIAN_POINT('',(8.09865121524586,4.5,16.3053789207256));
#654=CARTESIAN_POINT('',(7.87435773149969,4.5,16.1466830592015));
#655=CARTESIAN_POINT('',(7.42793360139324,4.5,15.826278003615));
#656=CARTESIAN_POINT('',(7.20580294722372,4.5,15.6645688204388));
#657=CARTESIAN_POINT('',(6.76333109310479,4.5,15.3388557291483));
#658=CARTESIAN_POINT('',(6.54298941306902,4.5,15.1748524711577));
#659=CARTESIAN_POINT('',(6.10341304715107,4.5,14.8453678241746));
#660=CARTESIAN_POINT('',(5.88417837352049,4.5,14.6798864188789));
#661=CARTESIAN_POINT('',(5.44597621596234,4.5,14.3486019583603));
#662=CARTESIAN_POINT('',(5.22700871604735,4.5,14.1827989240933));
#663=CARTESIAN_POINT('',(4.7881475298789,4.5,13.8524268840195));
#664=CARTESIAN_POINT('',(4.56825387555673,4.5,13.6878578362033));
#665=CARTESIAN_POINT('',(4.22599707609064,4.5,13.4359606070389));
#666=CARTESIAN_POINT('',(4.10454867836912,4.5,13.3473935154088));
#667=CARTESIAN_POINT('',(3.86050375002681,4.5,13.1718439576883));
#668=CARTESIAN_POINT('',(3.73790719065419,4.5,13.0848615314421));
#669=CARTESIAN_POINT('',(3.49095051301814,4.5,12.9129975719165));
#670=CARTESIAN_POINT('',(3.36658787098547,4.5,12.8281196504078));
#671=CARTESIAN_POINT('',(3.11579592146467,4.5,12.661467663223));
#672=CARTESIAN_POINT('',(2.98936669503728,4.5,12.5796934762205));
#673=CARTESIAN_POINT('',(2.73559541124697,4.5,12.421447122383));
#674=CARTESIAN_POINT('',(2.60828909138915,4.5,12.3449180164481));
#675=CARTESIAN_POINT('',(2.35045679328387,4.5,12.1973627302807));
#676=CARTESIAN_POINT('',(2.21993005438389,4.5,12.1263378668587));
#677=CARTESIAN_POINT('',(1.95547938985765,4.5,11.9918684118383));
#678=CARTESIAN_POINT('',(1.82156674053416,4.5,11.9284018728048));
#679=CARTESIAN_POINT('',(1.54956725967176,4.5,11.811188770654));
#680=CARTESIAN_POINT('',(1.41148300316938,4.5,11.7574363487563));
#681=CARTESIAN_POINT('',(1.16760292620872,4.5,11.6748301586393));
#682=CARTESIAN_POINT('',(1.06277320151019,4.5,11.6431384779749));
#683=CARTESIAN_POINT('',(0.850970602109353,4.5,11.5877982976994));
#684=CARTESIAN_POINT('',(0.743997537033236,4.5,11.5641505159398));
#685=CARTESIAN_POINT('',(0.528623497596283,4.5,11.5260430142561));
#686=CARTESIAN_POINT('',(0.420225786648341,4.5,11.5115651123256));
#687=CARTESIAN_POINT('',(0.202558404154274,4.5,11.4925018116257));
#688=CARTESIAN_POINT('',(0.0932888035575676,4.5,11.4879156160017));
#689=CARTESIAN_POINT('',(-0.125523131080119,4.5,11.4889012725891));
#690=CARTESIAN_POINT('',(-0.235065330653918,4.5,11.494502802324));
#691=CARTESIAN_POINT('',(-0.453184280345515,4.5,11.5155971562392));
#692=CARTESIAN_POINT('',(-0.561760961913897,4.5,11.5310906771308));
#693=CARTESIAN_POINT('',(-0.777434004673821,4.5,11.5711835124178));
#694=CARTESIAN_POINT('',(-0.884526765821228,4.5,11.5958019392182));
#695=CARTESIAN_POINT('',(-1.09652638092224,4.5,11.653010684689));
#696=CARTESIAN_POINT('',(-1.20143316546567,4.5,11.6856012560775));
#697=CARTESIAN_POINT('',(-1.54299128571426,4.5,11.8040046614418));
#698=CARTESIAN_POINT('',(-1.77469278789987,4.5,11.9041680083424));
#699=CARTESIAN_POINT('',(-2.11370642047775,4.5,12.0712278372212));
#700=CARTESIAN_POINT('',(-2.22542247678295,4.5,12.1298009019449));
#701=CARTESIAN_POINT('',(-2.4464125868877,4.5,12.2514053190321));
#702=CARTESIAN_POINT('',(-2.55568698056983,4.5,12.314436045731));
#703=CARTESIAN_POINT('',(-2.77325410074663,4.5,12.4446206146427));
#704=CARTESIAN_POINT('',(-2.88152520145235,4.5,12.5118101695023));
#705=CARTESIAN_POINT('',(-3.09631836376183,4.5,12.648928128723));
#706=CARTESIAN_POINT('',(-3.20284038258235,4.5,12.7188565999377));
#707=CARTESIAN_POINT('',(-3.41436916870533,4.5,12.8607497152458));
#708=CARTESIAN_POINT('',(-3.51937725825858,4.5,12.9327123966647));
#709=CARTESIAN_POINT('',(-3.72827441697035,4.5,13.0782322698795));
#710=CARTESIAN_POINT('',(-3.83216352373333,4.5,13.1517894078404));
#711=CARTESIAN_POINT('',(-4.05439859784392,4.5,13.3110694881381));
#712=CARTESIAN_POINT('',(-4.17260856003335,4.5,13.3969817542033));
#713=CARTESIAN_POINT('',(-4.4082339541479,4.5,13.5698902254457));
#714=CARTESIAN_POINT('',(-4.52564937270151,4.5,13.6568864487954));
#715=CARTESIAN_POINT('',(-4.87714945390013,4.5,13.9189069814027));
#716=CARTESIAN_POINT('',(-5.11047154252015,4.5,14.094951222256));
#717=CARTESIAN_POINT('',(-5.57685056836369,4.5,14.4474717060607));
#718=CARTESIAN_POINT('',(-5.80990745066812,4.5,14.6239480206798));
#719=CARTESIAN_POINT('',(-6.27690523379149,4.5,14.9757283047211));
#720=CARTESIAN_POINT('',(-6.51084612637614,4.5,15.1510322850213));
#721=CARTESIAN_POINT('',(-6.98047432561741,4.5,15.4993223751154));
#722=CARTESIAN_POINT('',(-7.21616173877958,4.5,15.6723083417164));
#723=CARTESIAN_POINT('',(-7.68986343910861,4.5,16.0150746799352));
#724=CARTESIAN_POINT('',(-7.92787774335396,4.5,16.1848550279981));
#725=CARTESIAN_POINT('',(-8.40663111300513,4.5,16.5205040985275));
#726=CARTESIAN_POINT('',(-8.64736999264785,4.5,16.6863730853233));
#727=CARTESIAN_POINT('',(-9.13186171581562,4.5,17.0136492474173));
#728=CARTESIAN_POINT('',(-9.37561458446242,4.5,17.1750563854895));
#729=CARTESIAN_POINT('',(-10.1060893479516,4.5,17.6482368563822));
#730=CARTESIAN_POINT('',(-10.5975021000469,4.5,17.952835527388));
#731=CARTESIAN_POINT('',(-11.5934664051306,4.5,18.5398125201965));
#732=CARTESIAN_POINT('',(-12.0980184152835,4.5,18.8221900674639));
#733=CARTESIAN_POINT('',(-13.1203636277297,4.5,19.362665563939));
#734=CARTESIAN_POINT('',(-13.6381640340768,4.5,19.6207499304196));
#735=CARTESIAN_POINT('',(-14.6860430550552,4.5,20.11066531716));
#736=CARTESIAN_POINT('',(-15.2161220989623,4.5,20.3424954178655));
#737=CARTESIAN_POINT('',(-16.5720374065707,4.5,20.8941289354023));
#738=CARTESIAN_POINT('',(-17.4055454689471,4.5,21.1953302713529));
#739=CARTESIAN_POINT('',(-19.0940463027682,4.5,21.7283556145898));
#740=CARTESIAN_POINT('',(-19.9490297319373,4.5,21.960209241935));
#741=CARTESIAN_POINT('',(-21.6811099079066,4.5,22.3529309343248));
#742=CARTESIAN_POINT('',(-22.5583149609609,4.5,22.5133231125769));
#743=CARTESIAN_POINT('',(-24.3233745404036,4.5,22.7586307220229));
#744=CARTESIAN_POINT('',(-25.2112306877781,4.5,22.8435345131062));
#745=CARTESIAN_POINT('',(-26.9908314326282,4.5,22.9363918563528));
#746=CARTESIAN_POINT('',(-27.8825753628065,4.5,22.9443581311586));
#747=CARTESIAN_POINT('',(-29.663358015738,4.5,22.8827217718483));
#748=CARTESIAN_POINT('',(-30.5523968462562,4.5,22.8131222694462));
#749=CARTESIAN_POINT('',(-32.31901432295,4.5,22.5966903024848));
#750=CARTESIAN_POINT('',(-33.1966141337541,4.5,22.4500307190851));
#751=CARTESIAN_POINT('',(-34.935590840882,4.5,22.080370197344));
#752=CARTESIAN_POINT('',(-35.796967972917,4.5,21.8573703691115));
#753=CARTESIAN_POINT('',(-37.4685359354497,4.5,21.3451591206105));
#754=CARTESIAN_POINT('',(-38.2794766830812,4.5,21.0583920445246));
#755=CARTESIAN_POINT('',(-39.873960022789,4.5,20.4167921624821));
#756=CARTESIAN_POINT('',(-40.6575033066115,4.5,20.0619610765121));
#757=CARTESIAN_POINT('',(-42.1918635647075,4.5,19.2864593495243));
#758=CARTESIAN_POINT('',(-42.9426616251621,4.5,18.8657512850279));
#759=CARTESIAN_POINT('',(-44.4054978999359,4.5,17.9616153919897));
#760=CARTESIAN_POINT('',(-45.1175362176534,4.5,17.4781877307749));
#761=CARTESIAN_POINT('',(-46.4882343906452,4.5,16.4590216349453));
#762=CARTESIAN_POINT('',(-47.1474852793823,4.5,15.9240778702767));
#763=CARTESIAN_POINT('',(-48.4183395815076,4.5,14.8003122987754));
#764=CARTESIAN_POINT('',(-49.0299435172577,4.5,14.2114910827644));
#765=CARTESIAN_POINT('',(-50.2009517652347,4.5,12.9842748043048));
#766=CARTESIAN_POINT('',(-50.7603665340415,4.5,12.3458897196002));
#767=CARTESIAN_POINT('',(-51.8230723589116,4.5,11.0239977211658));
#768=CARTESIAN_POINT('',(-52.3263634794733,4.5,10.3404908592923));
#769=CARTESIAN_POINT('',(-53.2706922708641,4.5,8.93692421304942));
#770=CARTESIAN_POINT('',(-53.7120407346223,4.5,8.21707350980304));
#771=CARTESIAN_POINT('',(-54.532396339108,4.5,6.74268654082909));
#772=CARTESIAN_POINT('',(-54.9114037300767,4.5,5.98815041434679));
#773=CARTESIAN_POINT('',(-55.6043575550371,4.5,4.44974284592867));
#774=CARTESIAN_POINT('',(-55.9183019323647,4.5,3.66587047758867));
#775=CARTESIAN_POINT('',(-56.478850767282,4.5,2.07440645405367));
#776=CARTESIAN_POINT('',(-56.7254552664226,4.5,1.26681481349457));
#777=CARTESIAN_POINT('',(-57.14904744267,4.5,-0.364399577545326));
#778=CARTESIAN_POINT('',(-57.3261971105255,4.5,-1.18798026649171));
#779=CARTESIAN_POINT('',(-57.6104293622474,4.5,-2.84714412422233));
#780=CARTESIAN_POINT('',(-57.7175120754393,4.5,-3.68272727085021));
#781=CARTESIAN_POINT('',(-57.8608403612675,4.5,-5.35993452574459));
#782=CARTESIAN_POINT('',(-57.8970869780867,4.5,-6.20155854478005));
#783=CARTESIAN_POINT('',(-57.8984858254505,4.5,-7.8848657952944));
#784=CARTESIAN_POINT('',(-57.8636380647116,4.5,-8.72654902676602));
#785=CARTESIAN_POINT('',(-57.7231579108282,4.5,-10.4032722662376));
#786=CARTESIAN_POINT('',(-57.6175852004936,4.5,-11.2383172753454));
#787=CARTESIAN_POINT('',(-57.3364725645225,4.5,-12.8965453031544));
#788=CARTESIAN_POINT('',(-57.1609326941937,4.5,-13.7197283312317));
#789=CARTESIAN_POINT('',(-56.7411440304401,4.5,-15.348385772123));
#790=CARTESIAN_POINT('',(-56.4968951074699,4.5,-16.1538601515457));
#791=CARTESIAN_POINT('',(-55.9414392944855,4.5,-17.7413808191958));
#792=CARTESIAN_POINT('',(-55.6302323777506,4.5,-18.5234270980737));
#793=CARTESIAN_POINT('',(-54.9430163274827,4.5,-20.0587116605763));
#794=CARTESIAN_POINT('',(-54.5669932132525,4.5,-20.8119436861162));
#795=CARTESIAN_POINT('',(-53.7528854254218,4.5,-22.28408588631));
#796=CARTESIAN_POINT('',(-53.3148007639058,4.5,-23.0029960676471));
#797=CARTESIAN_POINT('',(-52.3797121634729,4.5,-24.4014049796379));
#798=CARTESIAN_POINT('',(-51.8827089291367,4.5,-25.0809041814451));
#799=CARTESIAN_POINT('',(-50.8333343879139,4.5,-26.3957112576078));
#800=CARTESIAN_POINT('',(-50.2809630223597,4.5,-27.0310190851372));
#801=CARTESIAN_POINT('',(-49.1240210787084,4.5,-28.2538041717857));
#802=CARTESIAN_POINT('',(-48.519381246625,4.5,-28.841215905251));
#803=CARTESIAN_POINT('',(-47.2628697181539,4.5,-29.9631382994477));
#804=CARTESIAN_POINT('',(-46.6109980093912,4.5,-30.4976489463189));
#805=CARTESIAN_POINT('',(-45.2646445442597,4.5,-31.5100756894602));
#806=CARTESIAN_POINT('',(-44.5701605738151,4.5,-31.9879888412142));
#807=CARTESIAN_POINT('',(-43.1435639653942,4.5,-32.8838941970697));
#808=CARTESIAN_POINT('',(-42.4114512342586,4.5,-33.3018862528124));
#809=CARTESIAN_POINT('',(-40.912331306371,4.5,-34.0763837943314));
#810=CARTESIAN_POINT('',(-40.145216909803,4.5,-34.4326817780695));
#811=CARTESIAN_POINT('',(-38.5838228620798,4.5,-35.0797120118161));
#812=CARTESIAN_POINT('',(-37.7895432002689,4.5,-35.3704442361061));
#813=CARTESIAN_POINT('',(-36.1796169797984,4.5,-35.884414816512));
#814=CARTESIAN_POINT('',(-35.3639746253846,4.5,-36.1076663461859));
#815=CARTESIAN_POINT('',(-33.7169153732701,4.5,-36.485403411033));
#816=CARTESIAN_POINT('',(-32.8854983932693,4.5,-36.6398885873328));
#817=CARTESIAN_POINT('',(-31.2068509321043,4.5,-36.8801373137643));
#818=CARTESIAN_POINT('',(-30.3595503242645,4.5,-36.9654093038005));
#819=CARTESIAN_POINT('',(-28.6606960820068,4.5,-37.0651578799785));
#820=CARTESIAN_POINT('',(-27.8091424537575,4.5,-37.0796345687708));
#821=CARTESIAN_POINT('',(-26.5330536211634,4.5,-37.0485559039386));
#822=CARTESIAN_POINT('',(-26.107715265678,4.5,-37.0293778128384));
#823=CARTESIAN_POINT('',(-25.2581880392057,4.5,-36.9735158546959));
#824=CARTESIAN_POINT('',(-24.8339991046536,4.5,-36.9368329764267));
#825=CARTESIAN_POINT('',(-23.9875137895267,4.5,-36.8461059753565));
#826=CARTESIAN_POINT('',(-23.5652172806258,4.5,-36.7920630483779));
#827=CARTESIAN_POINT('',(-22.7231096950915,4.5,-36.6668007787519));
#828=CARTESIAN_POINT('',(-22.3032991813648,4.5,-36.5955776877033));
#829=CARTESIAN_POINT('',(-21.0326362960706,4.5,-36.3534077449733));
#830=CARTESIAN_POINT('',(-20.1867400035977,4.5,-36.1556925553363));
#831=CARTESIAN_POINT('',(-18.5137717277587,4.5,-35.6923115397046));
#832=CARTESIAN_POINT('',(-17.6867009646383,4.5,-35.4266413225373));
#833=CARTESIAN_POINT('',(-16.4648122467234,4.5,-34.9802120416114));
#834=CARTESIAN_POINT('',(-16.0610185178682,4.5,-34.8235901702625));
#835=CARTESIAN_POINT('',(-15.2598672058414,4.5,-34.494886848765));
#836=CARTESIAN_POINT('',(-14.8625080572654,4.5,-34.3228092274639));
#837=CARTESIAN_POINT('',(-14.0745563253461,4.5,-33.9637665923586));
#838=CARTESIAN_POINT('',(-13.6839641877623,4.5,-33.7768006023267));
#839=CARTESIAN_POINT('',(-12.909871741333,4.5,-33.3886824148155));
#840=CARTESIAN_POINT('',(-12.5263717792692,4.5,-33.1875295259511));
#841=CARTESIAN_POINT('',(-11.8207248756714,4.5,-32.801439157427));
#842=CARTESIAN_POINT('',(-11.4976102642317,4.5,-32.6182650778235));
#843=CARTESIAN_POINT('',(-10.8567820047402,4.5,-32.2426997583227));
#844=CARTESIAN_POINT('',(-10.539068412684,4.5,-32.0503084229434));
#845=CARTESIAN_POINT('',(-9.90902430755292,4.5,-31.6570700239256));
#846=CARTESIAN_POINT('',(-9.59669262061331,4.5,-31.4562248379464));
#847=CARTESIAN_POINT('',(-8.97708038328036,4.5,-31.0468984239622));
#848=CARTESIAN_POINT('',(-8.66979986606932,4.5,-30.838417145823));
#849=CARTESIAN_POINT('',(-8.05909926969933,4.5,-30.414391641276));
#850=CARTESIAN_POINT('',(-7.75568987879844,4.5,-30.1988320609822));
#851=CARTESIAN_POINT('',(-7.15264493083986,4.5,-29.7624945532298));
#852=CARTESIAN_POINT('',(-6.853009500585,4.5,-29.5417164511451));
#853=CARTESIAN_POINT('',(-6.25625428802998,4.5,-29.0968095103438));
#854=CARTESIAN_POINT('',(-5.95913448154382,4.5,-28.8726807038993));
#855=CARTESIAN_POINT('',(-5.51381007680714,4.5,-28.5360257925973));
#856=CARTESIAN_POINT('',(-5.36542874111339,4.5,-28.4237312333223));
#857=CARTESIAN_POINT('',(-5.06841921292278,4.5,-28.199468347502));
#858=CARTESIAN_POINT('',(-4.91979102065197,4.5,-28.0875000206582));
#859=CARTESIAN_POINT('',(-4.6673759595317,4.5,-27.8985569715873));
#860=CARTESIAN_POINT('',(-4.56376685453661,4.5,-27.8213455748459));
#861=CARTESIAN_POINT('',(-4.35603430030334,4.5,-27.6676191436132));
#862=CARTESIAN_POINT('',(-4.25191084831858,4.5,-27.5911041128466));
#863=CARTESIAN_POINT('',(-3.93839628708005,4.5,-27.3629654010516));
#864=CARTESIAN_POINT('',(-3.72792755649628,4.5,-27.2127984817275));
#865=CARTESIAN_POINT('',(-3.40866330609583,4.5,-26.9930527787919));
#866=CARTESIAN_POINT('',(-3.30173041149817,4.5,-26.920774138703));
#867=CARTESIAN_POINT('',(-3.08629576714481,4.5,-26.7785997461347));
#868=CARTESIAN_POINT('',(-2.97779412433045,4.5,-26.7087038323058));
#869=CARTESIAN_POINT('',(-2.75891564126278,4.5,-26.5720402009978));
#870=CARTESIAN_POINT('',(-2.64853991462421,4.5,-26.5052707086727));
#871=CARTESIAN_POINT('',(-2.42546973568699,4.5,-26.3757336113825));
#872=CARTESIAN_POINT('',(-2.31277560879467,4.5,-26.3129654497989));
#873=CARTESIAN_POINT('',(-2.08830306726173,4.5,-26.1944953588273));
#874=CARTESIAN_POINT('',(-1.97661068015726,4.5,-26.1386316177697));
#875=CARTESIAN_POINT('',(-1.75033429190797,4.5,-26.0330124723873));
#876=CARTESIAN_POINT('',(-1.63575004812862,4.5,-25.9832575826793));
#877=CARTESIAN_POINT('',(-1.40370429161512,4.5,-25.8914945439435));
#878=CARTESIAN_POINT('',(-1.28624783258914,4.5,-25.8494737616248));
#879=CARTESIAN_POINT('',(-1.04839229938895,4.5,-25.7748468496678));
#880=CARTESIAN_POINT('',(-0.927994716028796,4.5,-25.7422360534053));
#881=CARTESIAN_POINT('',(-0.704765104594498,4.5,-25.6926144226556));
#882=CARTESIAN_POINT('',(-0.602309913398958,4.5,-25.6739180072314));
#883=CARTESIAN_POINT('',(-0.396192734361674,4.5,-25.6451371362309));
#884=CARTESIAN_POINT('',(-0.292530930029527,4.5,-25.6350513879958));
#885=CARTESIAN_POINT('',(-0.0849035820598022,4.5,-25.6240115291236));
#886=CARTESIAN_POINT('',(0.0190610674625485,4.5,-25.6230408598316));
#887=CARTESIAN_POINT('',(0.226677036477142,4.5,-25.6302356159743));
#888=CARTESIAN_POINT('',(0.330328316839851,4.5,-25.6384021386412));
#889=CARTESIAN_POINT('',(0.558826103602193,4.5,-25.6661714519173));
#890=CARTESIAN_POINT('',(0.683419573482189,4.5,-25.687861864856));
#891=CARTESIAN_POINT('',(0.930070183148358,4.5,-25.7427051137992));
#892=CARTESIAN_POINT('',(1.05212589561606,4.5,-25.7758642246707));
#893=CARTESIAN_POINT('',(1.29373096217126,4.5,-25.8519835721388));
#894=CARTESIAN_POINT('',(1.41326576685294,4.5,-25.8949893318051));
#895=CARTESIAN_POINT('',(1.64912618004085,4.5,-25.9888630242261));
#896=CARTESIAN_POINT('',(1.76545261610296,4.5,-26.0397289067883));
#897=CARTESIAN_POINT('',(2.08022955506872,4.5,-26.1876658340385));
#898=CARTESIAN_POINT('',(2.27569357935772,4.5,-26.291055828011));
#899=CARTESIAN_POINT('',(2.65965824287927,4.5,-26.510129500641));
#900=CARTESIAN_POINT('',(2.84815185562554,4.5,-26.6258251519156));
#901=CARTESIAN_POINT('',(3.2206264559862,4.5,-26.865464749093));
#902=CARTESIAN_POINT('',(3.40459103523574,4.5,-26.9894339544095));
#903=CARTESIAN_POINT('',(3.76897708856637,4.5,-27.2422768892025));
#904=CARTESIAN_POINT('',(3.94939990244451,4.5,-27.3711487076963));
#905=CARTESIAN_POINT('',(4.30959038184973,4.5,-27.6329175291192));
#906=CARTESIAN_POINT('',(4.48934008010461,4.5,-27.7658391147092));
#907=CARTESIAN_POINT('',(4.84769993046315,4.5,-28.0332268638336));
#908=CARTESIAN_POINT('',(5.02631000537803,4.5,-28.1676931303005));
#909=CARTESIAN_POINT('',(5.38285547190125,4.5,-28.4368710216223));
#910=CARTESIAN_POINT('',(5.56079149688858,4.5,-28.5715818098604));
#911=CARTESIAN_POINT('',(5.91689994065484,4.5,-28.8406969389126));
#912=CARTESIAN_POINT('',(6.09507236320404,4.5,-28.9751012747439));
#913=CARTESIAN_POINT('',(6.51845290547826,4.5,-29.2927601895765));
#914=CARTESIAN_POINT('',(6.76396770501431,4.5,-29.4756076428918));
#915=CARTESIAN_POINT('',(7.25717026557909,4.5,-29.8383539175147));
#916=CARTESIAN_POINT('',(7.50485801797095,4.5,-30.0182527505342));
#917=CARTESIAN_POINT('',(8.00299141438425,4.5,-30.374186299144));
#918=CARTESIAN_POINT('',(8.25343697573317,4.5,-30.550221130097));
#919=CARTESIAN_POINT('',(8.75748514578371,4.5,-30.8977104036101));
#920=CARTESIAN_POINT('',(9.01108777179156,4.5,-31.0691648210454));
#921=CARTESIAN_POINT('',(9.77721510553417,4.5,-31.5758563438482));
#922=CARTESIAN_POINT('',(10.2949280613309,4.5,-31.9033270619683));
#923=CARTESIAN_POINT('',(11.3450798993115,4.5,-32.5338451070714));
#924=CARTESIAN_POINT('',(11.877519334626,4.5,-32.8368915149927));
#925=CARTESIAN_POINT('',(12.9541574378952,4.5,-33.4143106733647));
#926=CARTESIAN_POINT('',(13.4982794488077,4.5,-33.6888259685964));
#927=CARTESIAN_POINT('',(14.6002432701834,4.5,-34.2088544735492));
#928=CARTESIAN_POINT('',(15.1580853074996,4.5,-34.454367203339));
#929=CARTESIAN_POINT('',(16.286390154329,4.5,-34.9146730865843));
#930=CARTESIAN_POINT('',(16.8568541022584,4.5,-35.1294634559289));
#931=CARTESIAN_POINT('',(18.0088078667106,4.5,-35.5268449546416));
#932=CARTESIAN_POINT('',(18.5902966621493,4.5,-35.7094390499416));
#933=CARTESIAN_POINT('',(20.0165260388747,4.5,-36.1130976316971));
#934=CARTESIAN_POINT('',(20.8663068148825,4.5,-36.3166227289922));
#935=CARTESIAN_POINT('',(22.5794989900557,4.5,-36.652424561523));
#936=CARTESIAN_POINT('',(23.4429056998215,4.5,-36.7847252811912));
#937=CARTESIAN_POINT('',(25.1788937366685,4.5,-36.9764824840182));
#938=CARTESIAN_POINT('',(26.0514851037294,4.5,-37.0358485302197));
#939=CARTESIAN_POINT('',(27.7986551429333,4.5,-37.0803209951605));
#940=CARTESIAN_POINT('',(28.6732340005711,4.5,-37.0654201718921));
#941=CARTESIAN_POINT('',(30.4186265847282,4.5,-36.9608997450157));
#942=CARTESIAN_POINT('',(31.289436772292,4.5,-36.8712208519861));
#943=CARTESIAN_POINT('',(33.0201174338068,4.5,-36.6173414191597));
#944=CARTESIAN_POINT('',(33.8799881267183,4.5,-36.4531423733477));
#945=CARTESIAN_POINT('',(35.5821003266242,4.5,-36.0512093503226));
#946=CARTESIAN_POINT('',(36.4243470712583,4.5,-35.8134975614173));
#947=CARTESIAN_POINT('',(38.0851095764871,4.5,-35.266073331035));
#948=CARTESIAN_POINT('',(38.9036256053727,4.5,-34.9563617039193));
#949=CARTESIAN_POINT('',(40.4925929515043,4.5,-34.274865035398));
#950=CARTESIAN_POINT('',(41.2637115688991,4.5,-33.904634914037));
#951=CARTESIAN_POINT('',(42.7716979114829,4.5,-33.0999949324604));
#952=CARTESIAN_POINT('',(43.5085661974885,4.5,-32.6655861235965));
#953=CARTESIAN_POINT('',(44.9426667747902,4.5,-31.7356321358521));
#954=CARTESIAN_POINT('',(45.6398987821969,4.5,-31.2400865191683));
#955=CARTESIAN_POINT('',(46.9896031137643,4.5,-30.1913841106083));
#956=CARTESIAN_POINT('',(47.6420755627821,4.5,-29.6382274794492));
#957=CARTESIAN_POINT('',(48.891363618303,4.5,-28.4839074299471));
#958=CARTESIAN_POINT('',(49.4886578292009,4.5,-27.8832618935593));
#959=CARTESIAN_POINT('',(50.6303244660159,4.5,-26.6336248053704));
#960=CARTESIAN_POINT('',(51.1746972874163,4.5,-25.9846336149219));
#961=CARTESIAN_POINT('',(52.2065665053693,4.5,-24.642944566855));
#962=CARTESIAN_POINT('',(52.6940648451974,4.5,-23.9502482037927));
#963=CARTESIAN_POINT('',(53.6086759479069,4.5,-22.5260740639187));
#964=CARTESIAN_POINT('',(54.0357887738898,4.5,-21.7945963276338));
#965=CARTESIAN_POINT('',(54.8249218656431,4.5,-20.3011453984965));
#966=CARTESIAN_POINT('',(55.1872000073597,4.5,-19.5393084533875));
#967=CARTESIAN_POINT('',(55.8461836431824,4.5,-17.9877847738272));
#968=CARTESIAN_POINT('',(56.1428893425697,4.5,-17.1980981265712));
#969=CARTESIAN_POINT('',(56.668591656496,4.5,-15.5965045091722));
#970=CARTESIAN_POINT('',(56.8975886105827,4.5,-14.7845976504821));
#971=CARTESIAN_POINT('',(57.2862265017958,4.5,-13.144350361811));
#972=CARTESIAN_POINT('',(57.4458674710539,4.5,-12.3160099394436));
#973=CARTESIAN_POINT('',(57.6944225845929,4.5,-10.6502902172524));
#974=CARTESIAN_POINT('',(57.783461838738,4.5,-9.81292958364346));
#975=CARTESIAN_POINT('',(57.8906458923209,4.5,-8.13368390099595));
#976=CARTESIAN_POINT('',(57.9087907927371,4.5,-7.29179885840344));
#977=CARTESIAN_POINT('',(57.8740561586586,4.5,-5.60950140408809));
#978=CARTESIAN_POINT('',(57.8211771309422,4.5,-4.76908898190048));
#979=CARTESIAN_POINT('',(57.6447751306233,4.5,-3.09571117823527));
#980=CARTESIAN_POINT('',(57.5212521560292,4.5,-2.26274579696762));
#981=CARTESIAN_POINT('',(57.2045280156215,4.5,-0.610600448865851));
#982=CARTESIAN_POINT('',(57.0113616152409,4.5,0.208586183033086));
#983=CARTESIAN_POINT('',(56.5567261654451,4.5,1.82778068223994));
#984=CARTESIAN_POINT('',(56.2952571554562,4.5,2.6277885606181));
#985=CARTESIAN_POINT('',(55.7058883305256,4.5,4.2029541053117));
#986=CARTESIAN_POINT('',(55.3779880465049,4.5,4.97811159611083));
#987=CARTESIAN_POINT('',(54.6581068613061,4.5,6.49807652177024));
#988=CARTESIAN_POINT('',(54.2661259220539,4.5,7.24288393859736));
#989=CARTESIAN_POINT('',(53.4206580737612,4.5,8.69727722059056));
#990=CARTESIAN_POINT('',(52.9671375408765,4.5,9.40684353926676));
#991=CARTESIAN_POINT('',(52.002004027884,4.5,10.7853008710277));
#992=CARTESIAN_POINT('',(51.490391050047,4.5,11.4541918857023));
#993=CARTESIAN_POINT('',(50.4127466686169,4.5,12.7465698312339));
#994=CARTESIAN_POINT('',(49.8467165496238,4.5,13.3700578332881));
#995=CARTESIAN_POINT('',(48.6642736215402,4.5,14.5672713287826));
#996=CARTESIAN_POINT('',(48.0478607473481,4.5,15.1409967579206));
#997=CARTESIAN_POINT('',(46.7678900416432,4.5,16.2356730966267));
#998=CARTESIAN_POINT('',(46.1042486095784,4.5,16.7565262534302));
#999=CARTESIAN_POINT('',(44.7355620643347,4.5,17.7406453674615));
#1000=CARTESIAN_POINT('',(44.0305169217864,4.5,18.2039112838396));
#1001=CARTESIAN_POINT('',(42.5840120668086,4.5,19.0696922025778));
#1002=CARTESIAN_POINT('',(41.8425502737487,4.5,19.47220372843));
#1003=CARTESIAN_POINT('',(40.3285253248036,4.5,20.2137163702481));
#1004=CARTESIAN_POINT('',(39.5559621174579,4.5,20.5527173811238));
#1005=CARTESIAN_POINT('',(37.9819561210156,4.5,21.1662345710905));
#1006=CARTESIAN_POINT('',(37.1804070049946,4.5,21.4404779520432));
#1007=CARTESIAN_POINT('',(35.5571683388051,4.5,21.9209115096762));
#1008=CARTESIAN_POINT('',(34.7354786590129,4.5,22.1271012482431));
#1009=CARTESIAN_POINT('',(33.0778123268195,4.5,22.4701993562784));
#1010=CARTESIAN_POINT('',(32.2418364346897,4.5,22.607111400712));
#1011=CARTESIAN_POINT('',(30.5614263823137,4.5,22.8110090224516));
#1012=CARTESIAN_POINT('',(29.7169923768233,4.5,22.8779958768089));
#1013=CARTESIAN_POINT('',(28.0172278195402,4.5,22.9422784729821));
#1014=CARTESIAN_POINT('',(27.1618713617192,4.5,22.93888757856));
#1015=CARTESIAN_POINT('',(25.4543024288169,4.5,22.8612565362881));
#1016=CARTESIAN_POINT('',(24.6020902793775,4.5,22.7870092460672));
#1017=CARTESIAN_POINT('',(22.9069326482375,4.5,22.5688941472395));
#1018=CARTESIAN_POINT('',(22.0639845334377,4.5,22.4250466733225));
#1019=CARTESIAN_POINT('',(20.3927216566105,4.5,22.0696369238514));
#1020=CARTESIAN_POINT('',(19.5644013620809,4.5,21.8581008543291));
#1021=CARTESIAN_POINT('',(18.4649117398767,4.5,21.5303249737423));
#1022=CARTESIAN_POINT('',(18.1849661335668,4.5,21.4426914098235));
#1023=CARTESIAN_POINT('',(17.6275945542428,4.5,21.2599103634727));
#1024=CARTESIAN_POINT('',(17.350168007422,4.5,21.1647646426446));
#1025=CARTESIAN_POINT('',(16.7988253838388,4.5,20.967395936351));
#1026=CARTESIAN_POINT('',(16.5249010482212,4.5,20.8651959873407));
#1027=CARTESIAN_POINT('',(15.9797711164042,4.5,20.6535867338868));
#1028=CARTESIAN_POINT('',(15.7085662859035,4.5,20.5441754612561));
#1029=CARTESIAN_POINT('',(15.4388208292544,4.5,20.4312501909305));
#1030=B_SPLINE_CURVE_WITH_KNOTS('',3,(#642,#643,#644,#645,#646,#647,#648,#649,#650,#651,#652,
#653,#654,#655,#656,#657,#658,#659,#660,#661,#662,#663,#664,#665,#666,#667,#668,#669,#670,#671,
#672,#673,#674,#675,#676,#677,#678,#679,#680,#681,#682,#683,#684,#685,#686,#687,#688,#689,#690,
#691,#692,#693,#694,#695,#696,#697,#698,#699,#700,#701,#702,#703,#704,#705,#706,#707,#708,#709,
#710,#711,#712,#713,#714,#715,#716,#717,#718,#719,#720,#721,#722,#723,#724,#725,#726,#727,#728,
#729,#730,#731,#732,#733,#734,#735,#736,#737,#738,#739,#740,#741,#742,#743,#744,#745,#746,#747,
#748,#749,#750,#751,#752,#753,#754,#755,#756,#757,#758,#759,#760,#761,#762,#763,#764,#765,#766,
#767,#768,#769,#770,#771,#772,#773,#774,#775,#776,#777,#778,#779,#780,#781,#782,#783,#784,#785,
#786,#787,#788,#789,#790,#791,#792,#793,#794,#795,#796,#797,#798,#799,#800,#801,#802,#803,#804,
#805,#806,#807,#808,#809,#810,#811,#812,#813,#814,#815,#816,#817,#818,#819,#820,#821,#822,#823,
#824,#825,#826,#827,#828,#829,#830,#831,#832,#833,#834,#835,#836,#837,#838,#839,#840,#841,#842,
#843,#844,#845,#846,#847,#848,#849,#850,#851,#852,#853,#854,#855,#856,#857,#858,#859,#860,#861,
#862,#863,#864,#865,#866,#867,#868,#869,#870,#871,#872,#873,#874,#875,#876,#877,#878,#879,#880,
#881,#882,#883,#884,#885,#886,#887,#888,#889,#890,#891,#892,#893,#894,#895,#896,#897,#898,#899,
#900,#901,#902,#903,#904,#905,#906,#907,#908,#909,#910,#911,#912,#913,#914,#915,#916,#917,#918,
#919,#920,#921,#922,#923,#924,#925,#926,#927,#928,#929,#930,#931,#932,#933,#934,#935,#936,#937,
#938,#939,#940,#941,#942,#943,#944,#945,#946,#947,#948,#949,#950,#951,#952,#953,#954,#955,#956,
#957,#958,#959,#960,#961,#962,#963,#964,#965,#966,#967,#968,#969,#970,#971,#972,#973,#974,#975,
#976,#977,#978,#979,#980,#981,#982,#983,#984,#985,#986,#987,#988,#989,#990,#991,#992,#993,#994,
#995,#996,#997,#998,#999,#1000,#1001,#1002,#1003,#1004,#1005,#1006,#1007,#1008,#1009,#1010,
#1011,#1012,#1013,#1014,#1015,#1016,#1017,#1018,#1019,#1020,#1021,#1022,#1023,#1024,#1025,#1026,
#1027,#1028,#1029),.UNSPECIFIED.,.T.,.F.,(4,2,2,2,2,2,2,2,2,2,2,2,2,2,2,2,2,2,2,2,2,2,2,2,2,2,2,
2,2,2,2,2,2,2,2,2,2,2,2,2,2,2,2,2,2,2,2,2,2,2,2,2,2,2,2,2,2,2,2,2,2,2,2,2,2,2,2,2,2,2,2,2,2,2,2,
2,2,2,2,2,2,2,2,2,2,2,2,2,2,2,2,2,2,2,2,2,2,2,2,2,2,2,2,2,2,2,2,2,2,2,2,2,2,2,2,2,2,2,2,2,2,2,2,
2,2,2,2,2,2,2,2,2,2,2,2,2,2,2,2,2,2,2,2,2,2,2,2,2,2,2,2,2,2,2,2,2,2,2,2,2,2,2,2,2,2,2,2,2,2,2,2,
2,2,2,2,2,2,2,2,2,2,2,2,2,2,2,2,2,2,2,2,2,2,4),(0.,1.62807164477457,3.25642999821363,
4.88492937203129,6.51334393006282,8.16176131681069,8.98601514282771,9.8102659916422,
10.6342878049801,11.4583187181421,12.2822976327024,13.1062483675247,13.5571771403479,
14.0081172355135,14.4597840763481,14.9114332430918,15.3569463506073,15.8025657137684,
16.2468578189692,16.6908810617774,17.0191601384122,17.3474685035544,17.6751238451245,
18.0027527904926,18.3313376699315,18.659945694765,18.9892459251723,19.318556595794,
20.0734469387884,20.4518416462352,20.8301833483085,21.2124127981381,21.594651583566,
21.9765333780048,22.3584022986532,22.7967886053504,23.2351822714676,24.1120304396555,
24.9890355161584,25.8660324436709,26.7430832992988,27.6201405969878,28.4971384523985,
29.3741436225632,31.1080606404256,32.8420380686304,34.5769793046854,36.3119812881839,
38.9677083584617,41.6222994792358,44.2943134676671,46.9667394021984,49.6387234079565,
52.3105995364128,54.976506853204,57.642375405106,60.2197265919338,62.7970126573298,
65.3757681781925,67.9545168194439,70.4984377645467,73.0423308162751,75.58571307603,
78.1290924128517,80.6592156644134,83.1893287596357,85.7195218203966,88.249713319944,
90.7739679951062,93.2982180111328,95.8224308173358,98.3466433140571,100.868728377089,
103.390811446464,105.912899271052,108.434988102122,110.95762162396,113.480254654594,
116.002857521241,118.525463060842,121.051463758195,123.577465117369,126.10359783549,
128.629736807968,131.164213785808,133.698691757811,136.232674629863,138.766670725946,
141.318509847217,143.870345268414,145.147359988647,146.424302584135,147.70115723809,
148.97829073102,151.581248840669,154.184375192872,155.483418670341,156.782141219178,
158.080948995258,159.379820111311,160.493936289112,161.60806401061,162.721945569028,
163.835834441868,164.952323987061,166.068850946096,167.18536715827,167.743618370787,
168.301869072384,168.689510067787,169.077153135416,169.852689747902,170.239874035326,
170.627032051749,171.013967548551,171.40084910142,171.775354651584,172.149891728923,
172.523811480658,172.897545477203,173.209658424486,173.521724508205,173.833223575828,
174.144760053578,174.523525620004,174.902498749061,175.283260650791,175.663923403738,
176.326521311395,176.989769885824,177.655145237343,178.320263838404,178.99092115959,
179.661623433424,180.331156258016,181.000699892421,181.919051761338,182.837399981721,
183.755720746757,184.674046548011,186.51118318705,188.348388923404,190.175923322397,
192.003487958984,193.831218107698,195.658779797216,198.277105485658,200.894548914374,
203.515234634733,206.136175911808,208.75919723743,211.382165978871,214.004343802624,
216.626491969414,219.189590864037,221.752647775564,224.315723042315,226.878791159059,
229.416990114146,231.955170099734,234.493263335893,237.031353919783,239.559113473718,
242.086865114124,244.614604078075,247.142341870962,249.665590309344,252.188835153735,
254.712061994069,257.235288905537,259.757257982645,262.279225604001,264.80121103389,
267.323197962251,269.846568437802,272.369938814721,274.893249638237,277.416563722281,
279.944461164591,282.472360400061,285.000404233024,287.528452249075,290.066967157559,
292.60549840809,295.143894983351,297.682245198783,300.245372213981,302.808757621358,
305.371394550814,307.933040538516,308.812996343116,309.692746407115,310.56974830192,
311.446990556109),.UNSPECIFIED.);
#1031=EDGE_CURVE('E261',#639,#536,#1030,.T.);
#1032=ORIENTED_EDGE('',*,*,#1031,.T.);
#1033=ORIENTED_EDGE('',*,*,#537,.T.);
#1034=ORIENTED_EDGE('',*,*,#432,.T.);
#1035=ORIENTED_EDGE('',*,*,#208,.F.);
#1036=ORIENTED_EDGE('',*,*,#376,.F.);
#1037=DIRECTION('',(0.707106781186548,0.,-0.707106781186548));
#1038=VECTOR('',#1037,1.);
#1039=CARTESIAN_POINT('',(27.1888202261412,4.5,18.3111797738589));
#1040=LINE('',#1039,#1038);
#1041=EDGE_CURVE('E470',#606,#369,#1040,.T.);
#1042=ORIENTED_EDGE('',*,*,#1041,.F.);
#1043=EDGE_LOOP('',(#608,#641,#1032,#1033,#1034,#1035,#1036,#1042));
#1044=FACE_BOUND('',#1043,.T.);
#1045=ADVANCED_FACE('F166',(#1044),#597,.F.);
#1046=CARTESIAN_POINT('',(25.5,-4.5,0.));
#1047=DIRECTION('',(0.,1.,0.));
#1048=DIRECTION('',(-1.,0.,0.));
#1049=AXIS2_PLACEMENT_3D('',#1046,#1047,#1048);
#1050=PLANE('',#1049);
#1051=CARTESIAN_POINT('',(15.4388208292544,-4.5,20.4312501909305));
#1052=CARTESIAN_POINT('',(15.8561117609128,-4.5,20.6059409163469));
#1053=CARTESIAN_POINT('',(16.2769268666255,-4.5,20.7722358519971));
#1054=CARTESIAN_POINT('',(17.1250355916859,-4.5,21.087419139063));
#1055=CARTESIAN_POINT('',(17.5523297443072,-4.5,21.236306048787));
#1056=CARTESIAN_POINT('',(18.8429460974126,-4.5,21.6559972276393));
#1057=CARTESIAN_POINT('',(19.7152063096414,-4.5,21.8999177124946));
#1058=CARTESIAN_POINT('',(21.4781682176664,-4.5,22.3126126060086));
#1059=CARTESIAN_POINT('',(22.3688874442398,-4.5,22.4813117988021));
#1060=CARTESIAN_POINT('',(24.1616685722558,-4.5,22.7408279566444));
#1061=CARTESIAN_POINT('',(25.0637305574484,-4.5,22.8316443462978));
#1062=CARTESIAN_POINT('',(26.86675363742,-4.5,22.9335126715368));
#1063=CARTESIAN_POINT('',(27.7676869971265,-4.5,22.945054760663));
#1064=CARTESIAN_POINT('',(29.5671078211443,-4.5,22.8889694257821));
#1065=CARTESIAN_POINT('',(30.465595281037,-4.5,22.8213418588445));
#1066=CARTESIAN_POINT('',(32.2530264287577,-4.5,22.6069888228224));
#1067=CARTESIAN_POINT('',(33.1419708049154,-4.5,22.4602690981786));
#1068=CARTESIAN_POINT('',(34.9033276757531,-4.5,22.088539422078));
#1069=CARTESIAN_POINT('',(35.7757407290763,-4.5,21.8635321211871));
#1070=CARTESIAN_POINT('',(37.4586142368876,-4.5,21.3485228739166));
#1071=CARTESIAN_POINT('',(38.2701017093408,-4.5,21.0618710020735));
#1072=CARTESIAN_POINT('',(39.8656672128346,-4.5,20.4204192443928));
#1073=CARTESIAN_POINT('',(40.6497461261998,-4.5,20.0656215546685));
#1074=CARTESIAN_POINT('',(42.1845826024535,-4.5,19.290397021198));
#1075=CARTESIAN_POINT('',(42.9353461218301,-4.5,18.8699819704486));
#1076=CARTESIAN_POINT('',(44.3981481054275,-4.5,17.9664459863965));
#1077=CARTESIAN_POINT('',(45.1101866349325,-4.5,17.4833251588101));
#1078=CARTESIAN_POINT('',(46.4809898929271,-4.5,16.4647276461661));
#1079=CARTESIAN_POINT('',(47.1403408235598,-4.5,15.9300396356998));
#1080=CARTESIAN_POINT('',(48.4114215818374,-4.5,14.8067814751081));
#1081=CARTESIAN_POINT('',(49.0231519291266,-4.5,14.2182119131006));
#1082=CARTESIAN_POINT('',(50.1945633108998,-4.5,12.9913621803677));
#1083=CARTESIAN_POINT('',(50.7542437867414,-4.5,12.3530814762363));
#1084=CARTESIAN_POINT('',(51.8174825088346,-4.5,11.0313705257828));
#1085=CARTESIAN_POINT('',(52.3210408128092,-4.5,10.3479403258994));
#1086=CARTESIAN_POINT('',(53.2658616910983,-4.5,8.94455830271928));
#1087=CARTESIAN_POINT('',(53.7074400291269,-4.5,8.22481904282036));
#1088=CARTESIAN_POINT('',(54.5282621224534,-4.5,6.75063433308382));
#1089=CARTESIAN_POINT('',(54.9075061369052,-4.5,5.99618902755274));
#1090=CARTESIAN_POINT('',(55.60091969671,-4.5,4.45798300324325));
#1091=CARTESIAN_POINT('',(55.9150906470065,-4.5,3.67422291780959));
#1092=CARTESIAN_POINT('',(56.476102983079,-4.5,2.08296442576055));
#1093=CARTESIAN_POINT('',(56.7229444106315,-4.5,1.2754660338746));
#1094=CARTESIAN_POINT('',(57.1470226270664,-4.5,-0.355597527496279));
#1095=CARTESIAN_POINT('',(57.3244200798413,-4.5,-1.17912092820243));
#1096=CARTESIAN_POINT('',(57.6091522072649,-4.5,-2.83819127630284));
#1097=CARTESIAN_POINT('',(57.7164870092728,-4.5,-3.67373820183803));
#1098=CARTESIAN_POINT('',(57.8603228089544,-4.5,-5.35090423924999));
#1099=CARTESIAN_POINT('',(57.8968240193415,-4.5,-6.1925233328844));
#1100=CARTESIAN_POINT('',(57.8987310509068,-4.5,-7.87584219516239));
#1101=CARTESIAN_POINT('',(57.8641368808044,-4.5,-8.71754196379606));
#1102=CARTESIAN_POINT('',(57.7241612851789,-4.5,-10.3943146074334));
#1103=CARTESIAN_POINT('',(57.6188399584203,-4.5,-11.2293925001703));
#1104=CARTESIAN_POINT('',(57.3382263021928,-4.5,-12.8877073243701));
#1105=CARTESIAN_POINT('',(57.1629340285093,-4.5,-13.7109442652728));
#1106=CARTESIAN_POINT('',(56.7436354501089,-4.5,-15.3397284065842));
#1107=CARTESIAN_POINT('',(56.4996291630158,-4.5,-16.14527561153));
#1108=CARTESIAN_POINT('',(55.9446516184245,-4.5,-17.7329621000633));
#1109=CARTESIAN_POINT('',(55.6336803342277,-4.5,-18.5151013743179));
#1110=CARTESIAN_POINT('',(54.946926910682,-4.5,-20.0505914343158));
#1111=CARTESIAN_POINT('',(54.5711307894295,-4.5,-20.8039359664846));
#1112=CARTESIAN_POINT('',(53.7574666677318,-4.5,-22.2763218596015));
#1113=CARTESIAN_POINT('',(53.3195986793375,-4.5,-22.9953632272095));
#1114=CARTESIAN_POINT('',(52.3849314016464,-4.5,-24.3940524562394));
#1115=CARTESIAN_POINT('',(51.8881327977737,-4.5,-25.0737007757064));
#1116=CARTESIAN_POINT('',(50.8391541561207,-4.5,-26.388822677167));
#1117=CARTESIAN_POINT('',(50.2869740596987,-4.5,-27.0242962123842));
#1118=CARTESIAN_POINT('',(49.1304008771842,-4.5,-28.2474275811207));
#1119=CARTESIAN_POINT('',(48.5259385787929,-4.5,-28.8350199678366));
#1120=CARTESIAN_POINT('',(47.2697662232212,-4.5,-29.9573178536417));
#1121=CARTESIAN_POINT('',(46.6180561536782,-4.5,-30.4920233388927));
#1122=CARTESIAN_POINT('',(45.272009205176,-4.5,-31.5048523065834));
#1123=CARTESIAN_POINT('',(44.5776701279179,-4.5,-31.9829728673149));
#1124=CARTESIAN_POINT('',(43.1513452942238,-4.5,-32.8793042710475));
#1125=CARTESIAN_POINT('',(42.4193594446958,-4.5,-33.2975149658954));
#1126=CARTESIAN_POINT('',(40.920476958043,-4.5,-34.0724589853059));
#1127=CARTESIAN_POINT('',(40.1534731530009,-4.5,-34.4289850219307));
#1128=CARTESIAN_POINT('',(38.5922807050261,-4.5,-35.0764796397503));
#1129=CARTESIAN_POINT('',(37.798092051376,-4.5,-35.367448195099));
#1130=CARTESIAN_POINT('',(36.1883263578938,-4.5,-35.8818982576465));
#1131=CARTESIAN_POINT('',(35.3727534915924,-4.5,-36.1053928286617));
#1132=CARTESIAN_POINT('',(33.7258125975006,-4.5,-36.4836202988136));
#1133=CARTESIAN_POINT('',(32.8944444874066,-4.5,-36.638352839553));
#1134=CARTESIAN_POINT('',(31.2158772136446,-4.5,-36.8790999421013));
#1135=CARTESIAN_POINT('',(30.3686078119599,-4.5,-36.9646232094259));
#1136=CARTESIAN_POINT('',(28.6697949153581,-4.5,-37.0648751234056));
#1137=CARTESIAN_POINT('',(27.818251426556,-4.5,-37.0796038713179));
#1138=CARTESIAN_POINT('',(26.5421645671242,-4.5,-37.0489022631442));
#1139=CARTESIAN_POINT('',(26.1168258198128,-4.5,-37.0298498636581));
#1140=CARTESIAN_POINT('',(25.2672926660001,-4.5,-36.9742388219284));
#1141=CARTESIAN_POINT('',(24.8430981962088,-4.5,-36.9376811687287));
#1142=CARTESIAN_POINT('',(23.9965967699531,-4.5,-36.8472038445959));
#1143=CARTESIAN_POINT('',(23.5742896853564,-4.5,-36.7932853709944));
#1144=CARTESIAN_POINT('',(22.7321559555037,-4.5,-36.6682709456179));
#1145=CARTESIAN_POINT('',(22.3123298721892,-4.5,-36.5971712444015));
#1146=CARTESIAN_POINT('',(21.0416320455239,-4.5,-36.3553778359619));
#1147=CARTESIAN_POINT('',(20.195708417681,-4.5,-36.1579152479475));
#1148=CARTESIAN_POINT('',(18.5226659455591,-4.5,-35.6950336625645));
#1149=CARTESIAN_POINT('',(17.6955483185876,-4.5,-35.4296102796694));
#1150=CARTESIAN_POINT('',(16.4735693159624,-4.5,-34.9835410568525));
#1151=CARTESIAN_POINT('',(16.0697387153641,-4.5,-34.8270358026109));
#1152=CARTESIAN_POINT('',(15.2685100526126,-4.5,-34.4985621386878));
#1153=CARTESIAN_POINT('',(14.8711104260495,-4.5,-34.3265975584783));
#1154=CARTESIAN_POINT('',(14.0830747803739,-4.5,-33.9677768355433));
#1155=CARTESIAN_POINT('',(13.6924392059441,-4.5,-33.7809197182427));
#1156=CARTESIAN_POINT('',(12.9182576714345,-4.5,-33.3930142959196));
#1157=CARTESIAN_POINT('',(12.5347120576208,-4.5,-33.1919653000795));
#1158=CARTESIAN_POINT('',(11.8291261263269,-4.5,-32.8061426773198));
#1159=CARTESIAN_POINT('',(11.506115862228,-4.5,-32.6231376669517));
#1160=CARTESIAN_POINT('',(10.8654914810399,-4.5,-32.2479132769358));
#1161=CARTESIAN_POINT('',(10.5478774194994,-4.5,-32.0556938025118));
#1162=CARTESIAN_POINT('',(9.91802916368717,-4.5,-31.6627998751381));
#1163=CARTESIAN_POINT('',(9.60579379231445,-4.5,-31.4621273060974));
#1164=CARTESIAN_POINT('',(8.98637291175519,-4.5,-31.0531438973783));
#1165=CARTESIAN_POINT('',(8.67918743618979,-4.5,-30.8448330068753));
#1166=CARTESIAN_POINT('',(8.06869277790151,-4.5,-30.4211518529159));
#1167=CARTESIAN_POINT('',(7.76539408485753,-4.5,-30.2057665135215));
#1168=CARTESIAN_POINT('',(7.16257759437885,-4.5,-29.769765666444));
#1169=CARTESIAN_POINT('',(6.86305992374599,-4.5,-29.5491499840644));
#1170=CARTESIAN_POINT('',(6.26655458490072,-4.5,-29.104545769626));
#1171=CARTESIAN_POINT('',(5.969566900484,-4.5,-28.8805572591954));
#1172=CARTESIAN_POINT('',(5.52446235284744,-4.5,-28.5440840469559));
#1173=CARTESIAN_POINT('',(5.37615787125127,-4.5,-28.4318452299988));
#1174=CARTESIAN_POINT('',(5.07931179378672,-4.5,-28.207680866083));
#1175=CARTESIAN_POINT('',(4.93077019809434,-4.5,-28.0957553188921));
#1176=CARTESIAN_POINT('',(4.67855918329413,-4.5,-27.9069047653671));
#1177=CARTESIAN_POINT('',(4.57506434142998,-4.5,-27.8297473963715));
#1178=CARTESIAN_POINT('',(4.3675683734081,-4.5,-27.6761177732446));
#1179=CARTESIAN_POINT('',(4.26356724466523,-4.5,-27.5996455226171));
#1180=CARTESIAN_POINT('',(3.95043632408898,-4.5,-27.3716155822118));
#1181=CARTESIAN_POINT('',(3.74024377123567,-4.5,-27.2214937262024));
#1182=CARTESIAN_POINT('',(3.42143125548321,-4.5,-27.0017423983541));
#1183=CARTESIAN_POINT('',(3.31465242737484,-4.5,-26.9294480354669));
#1184=CARTESIAN_POINT('',(3.09954264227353,-4.5,-26.7872121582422));
#1185=CARTESIAN_POINT('',(2.99121178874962,-4.5,-26.7172704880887));
#1186=CARTESIAN_POINT('',(2.77269271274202,-4.5,-26.5804757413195));
#1187=CARTESIAN_POINT('',(2.66250556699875,-4.5,-26.5136209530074));
#1188=CARTESIAN_POINT('',(2.43983349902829,-4.5,-26.3838630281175));
#1189=CARTESIAN_POINT('',(2.32734889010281,-4.5,-26.3209593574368));
#1190=CARTESIAN_POINT('',(2.1029232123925,-4.5,-26.2019540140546));
#1191=CARTESIAN_POINT('',(1.99105856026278,-4.5,-26.1457092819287));
#1192=CARTESIAN_POINT('',(1.76443399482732,-4.5,-26.0392996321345));
#1193=CARTESIAN_POINT('',(1.64967383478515,-4.5,-25.9891352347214));
#1194=CARTESIAN_POINT('',(1.41726304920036,-4.5,-25.8965271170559));
#1195=CARTESIAN_POINT('',(1.29961747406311,-4.5,-25.8540708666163));
#1196=CARTESIAN_POINT('',(1.06135919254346,-4.5,-25.7785557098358));
#1197=CARTESIAN_POINT('',(0.940747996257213,-4.5,-25.7454921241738));
#1198=CARTESIAN_POINT('',(0.717325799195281,-4.5,-25.695093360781));
#1199=CARTESIAN_POINT('',(0.614901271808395,-4.5,-25.6760546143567));
#1200=CARTESIAN_POINT('',(0.40881703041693,-4.5,-25.6465654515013));
#1201=CARTESIAN_POINT('',(0.305157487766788,-4.5,-25.6361138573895));
#1202=CARTESIAN_POINT('',(0.0974730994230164,-4.5,-25.6243341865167));
#1203=CARTESIAN_POINT('',(-0.0065509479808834,-4.5,-25.6229922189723));
#1204=CARTESIAN_POINT('',(-0.214314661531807,-4.5,-25.6294656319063));
#1205=CARTESIAN_POINT('',(-0.318054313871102,-4.5,-25.6372814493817));
#1206=CARTESIAN_POINT('',(-0.524007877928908,-4.5,-25.6616120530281));
#1207=CARTESIAN_POINT('',(-0.626226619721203,-4.5,-25.6780865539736));
#1208=CARTESIAN_POINT('',(-0.829059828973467,-4.5,-25.7189487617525));
#1209=CARTESIAN_POINT('',(-0.929674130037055,-4.5,-25.7433372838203));
#1210=CARTESIAN_POINT('',(-1.12915582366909,-4.5,-25.7991183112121));
#1211=CARTESIAN_POINT('',(-1.22801896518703,-4.5,-25.8305258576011));
#1212=CARTESIAN_POINT('',(-1.42359250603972,-4.5,-25.8992802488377));
#1213=CARTESIAN_POINT('',(-1.5203036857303,-4.5,-25.9366248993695));
#1214=CARTESIAN_POINT('',(-1.83088552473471,-4.5,-26.0659040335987));
#1215=CARTESIAN_POINT('',(-2.04057438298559,-4.5,-26.1678740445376));
#1216=CARTESIAN_POINT('',(-2.45140510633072,-4.5,-26.3879372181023));
#1217=CARTESIAN_POINT('',(-2.65253263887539,-4.5,-26.5060561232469));
#1218=CARTESIAN_POINT('',(-3.04941801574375,-4.5,-26.7530211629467));
#1219=CARTESIAN_POINT('',(-3.24514386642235,-4.5,-26.8819181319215));
#1220=CARTESIAN_POINT('',(-3.63213393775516,-4.5,-27.1459110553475));
#1221=CARTESIAN_POINT('',(-3.82340085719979,-4.5,-27.2810031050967));
#1222=CARTESIAN_POINT('',(-4.20606755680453,-4.5,-27.556898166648));
#1223=CARTESIAN_POINT('',(-4.39742748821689,-4.5,-27.6977560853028));
#1224=CARTESIAN_POINT('',(-4.77871648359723,-4.5,-27.9814300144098));
#1225=CARTESIAN_POINT('',(-4.96864537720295,-4.5,-28.1242462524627));
#1226=CARTESIAN_POINT('',(-5.34749309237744,-4.5,-28.4101054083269));
#1227=CARTESIAN_POINT('',(-5.53641325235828,-4.5,-28.5531465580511));
#1228=CARTESIAN_POINT('',(-5.91450376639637,-4.5,-28.8388977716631));
#1229=CARTESIAN_POINT('',(-6.10367412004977,-4.5,-28.9816078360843));
#1230=CARTESIAN_POINT('',(-6.53425921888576,-4.5,-29.3045463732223));
#1231=CARTESIAN_POINT('',(-6.77592084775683,-4.5,-29.4844469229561));
#1232=CARTESIAN_POINT('',(-7.26135519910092,-4.5,-29.8413822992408));
#1233=CARTESIAN_POINT('',(-7.50512791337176,-4.5,-30.0184171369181));
#1234=CARTESIAN_POINT('',(-7.99534334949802,-4.5,-30.3687495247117));
#1235=CARTESIAN_POINT('',(-8.24178601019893,-4.5,-30.5420471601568));
#1236=CARTESIAN_POINT('',(-8.7377223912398,-4.5,-30.8842194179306));
#1237=CARTESIAN_POINT('',(-8.98721612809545,-4.5,-31.0530940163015));
#1238=CARTESIAN_POINT('',(-9.74101391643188,-4.5,-31.5524332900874));
#1239=CARTESIAN_POINT('',(-10.2503354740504,-4.5,-31.8753976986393));
#1240=CARTESIAN_POINT('',(-11.2832362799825,-4.5,-32.4977580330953));
#1241=CARTESIAN_POINT('',(-11.8068159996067,-4.5,-32.79715317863));
#1242=CARTESIAN_POINT('',(-12.8640779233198,-4.5,-33.3675513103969));
#1243=CARTESIAN_POINT('',(-13.3976519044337,-4.5,-33.6387543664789));
#1244=CARTESIAN_POINT('',(-14.4780934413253,-4.5,-34.1533127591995));
#1245=CARTESIAN_POINT('',(-15.0249611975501,-4.5,-34.39666767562));
#1246=CARTESIAN_POINT('',(-16.1309303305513,-4.5,-34.8538591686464));
#1247=CARTESIAN_POINT('',(-16.6900317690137,-4.5,-35.0676955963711));
#1248=CARTESIAN_POINT('',(-17.8190243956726,-4.5,-35.4644474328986));
#1249=CARTESIAN_POINT('',(-18.3889146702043,-4.5,-35.6473654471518));
#1250=CARTESIAN_POINT('',(-19.8024066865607,-4.5,-36.057952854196));
#1251=CARTESIAN_POINT('',(-20.6513504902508,-4.5,-36.2675140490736));
#1252=CARTESIAN_POINT('',(-22.3633995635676,-4.5,-36.6154834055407));
#1253=CARTESIAN_POINT('',(-23.2265005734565,-4.5,-36.7539125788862));
#1254=CARTESIAN_POINT('',(-24.9625737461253,-4.5,-36.9579723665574));
#1255=CARTESIAN_POINT('',(-25.8355583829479,-4.5,-37.0234973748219));
#1256=CARTESIAN_POINT('',(-27.5840274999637,-4.5,-37.0802106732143));
#1257=CARTESIAN_POINT('',(-28.4595121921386,-4.5,-37.0713924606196));
#1258=CARTESIAN_POINT('',(-30.2071469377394,-4.5,-36.9789130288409));
#1259=CARTESIAN_POINT('',(-31.0792942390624,-4.5,-36.8951996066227));
#1260=CARTESIAN_POINT('',(-32.8131528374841,-4.5,-36.6530782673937));
#1261=CARTESIAN_POINT('',(-33.6748643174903,-4.5,-36.4946716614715));
#1262=CARTESIAN_POINT('',(-35.3811752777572,-4.5,-36.1040918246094));
#1263=CARTESIAN_POINT('',(-36.2257791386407,-4.5,-35.871937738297));
#1264=CARTESIAN_POINT('',(-37.8917098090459,-4.5,-35.3353565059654));
#1265=CARTESIAN_POINT('',(-38.7130369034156,-4.5,-35.0309302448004));
#1266=CARTESIAN_POINT('',(-40.3075403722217,-4.5,-34.3597619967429));
#1267=CARTESIAN_POINT('',(-41.0813904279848,-4.5,-33.9946194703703));
#1268=CARTESIAN_POINT('',(-42.5952551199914,-4.5,-33.1998923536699));
#1269=CARTESIAN_POINT('',(-43.335270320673,-4.5,-32.7703088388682));
#1270=CARTESIAN_POINT('',(-44.776026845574,-4.5,-31.8497253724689));
#1271=CARTESIAN_POINT('',(-45.4767694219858,-4.5,-31.3587273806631));
#1272=CARTESIAN_POINT('',(-46.8338604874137,-4.5,-30.3187935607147));
#1273=CARTESIAN_POINT('',(-47.4902091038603,-4.5,-29.7698578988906));
#1274=CARTESIAN_POINT('',(-48.7474352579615,-4.5,-28.6236837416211));
#1275=CARTESIAN_POINT('',(-49.3487966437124,-4.5,-28.026975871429));
#1276=CARTESIAN_POINT('',(-50.4989132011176,-4.5,-26.784853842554));
#1277=CARTESIAN_POINT('',(-51.0476687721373,-4.5,-26.1394400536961));
#1278=CARTESIAN_POINT('',(-52.0885948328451,-4.5,-24.8045090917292));
#1279=CARTESIAN_POINT('',(-52.5807663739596,-4.5,-24.1149927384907));
#1280=CARTESIAN_POINT('',(-53.5049709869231,-4.5,-22.6967684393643));
#1281=CARTESIAN_POINT('',(-53.937004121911,-4.5,-21.9680605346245));
#1282=CARTESIAN_POINT('',(-54.7361398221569,-4.5,-20.4797620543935));
#1283=CARTESIAN_POINT('',(-55.1035038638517,-4.5,-19.7203118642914));
#1284=CARTESIAN_POINT('',(-55.772840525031,-4.5,-18.1731233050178));
#1285=CARTESIAN_POINT('',(-56.0748133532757,-4.5,-17.3853850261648));
#1286=CARTESIAN_POINT('',(-56.6111913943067,-4.5,-15.7872408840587));
#1287=CARTESIAN_POINT('',(-56.8455973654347,-4.5,-14.976835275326));
#1288=CARTESIAN_POINT('',(-57.2451582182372,-4.5,-13.3391280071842));
#1289=CARTESIAN_POINT('',(-57.4103131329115,-4.5,-12.5118263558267));
#1290=CARTESIAN_POINT('',(-57.669947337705,-4.5,-10.8477391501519));
#1291=CARTESIAN_POINT('',(-57.7645538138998,-4.5,-10.0109734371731));
#1292=CARTESIAN_POINT('',(-57.8829015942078,-4.5,-8.33244621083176));
#1293=CARTESIAN_POINT('',(-57.9066430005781,-4.5,-7.49068470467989));
#1294=CARTESIAN_POINT('',(-57.8830903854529,-4.5,-5.80815814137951));
#1295=CARTESIAN_POINT('',(-57.835796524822,-4.5,-4.96739308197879));
#1296=CARTESIAN_POINT('',(-57.6705131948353,-4.5,-3.29284080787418));
#1297=CARTESIAN_POINT('',(-57.552523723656,-4.5,-2.45905359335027));
#1298=CARTESIAN_POINT('',(-57.2467751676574,-4.5,-0.804816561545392));
#1299=CARTESIAN_POINT('',(-57.0590521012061,-4.5,0.0156399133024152));
#1300=CARTESIAN_POINT('',(-56.6151755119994,-4.5,1.6378275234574));
#1301=CARTESIAN_POINT('',(-56.3590220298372,-4.5,2.4395586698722));
#1302=CARTESIAN_POINT('',(-55.780122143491,-4.5,4.01860141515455));
#1303=CARTESIAN_POINT('',(-55.4573761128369,-4.5,4.79591315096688));
#1304=CARTESIAN_POINT('',(-54.7476024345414,-4.5,6.32061202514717));
#1305=CARTESIAN_POINT('',(-54.3605747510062,-4.5,7.06799914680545));
#1306=CARTESIAN_POINT('',(-53.5247939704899,-4.5,8.5279349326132));
#1307=CARTESIAN_POINT('',(-53.0760092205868,-4.5,9.24046547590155));
#1308=CARTESIAN_POINT('',(-52.1200808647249,-4.5,10.625239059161));
#1309=CARTESIAN_POINT('',(-51.6129372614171,-4.5,11.2974821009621));
#1310=CARTESIAN_POINT('',(-50.5439125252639,-4.5,12.5969523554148));
#1311=CARTESIAN_POINT('',(-49.9820305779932,-4.5,13.2241788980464));
#1312=CARTESIAN_POINT('',(-48.8075520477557,-4.5,14.4292015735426));
#1313=CARTESIAN_POINT('',(-48.1949553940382,-4.5,15.0069976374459));
#1314=CARTESIAN_POINT('',(-46.9222654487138,-4.5,16.1101243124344));
#1315=CARTESIAN_POINT('',(-46.2620879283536,-4.5,16.6353577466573));
#1316=CARTESIAN_POINT('',(-44.8999454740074,-4.5,17.6285071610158));
#1317=CARTESIAN_POINT('',(-44.1979805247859,-4.5,18.0964231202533));
#1318=CARTESIAN_POINT('',(-42.7573041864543,-4.5,18.9716949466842));
#1319=CARTESIAN_POINT('',(-42.01859441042,-4.5,19.3790534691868));
#1320=CARTESIAN_POINT('',(-40.5096556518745,-4.5,20.1304713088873));
#1321=CARTESIAN_POINT('',(-39.7394265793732,-4.5,20.474530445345));
#1322=CARTESIAN_POINT('',(-38.1697423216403,-4.5,21.0983266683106));
#1323=CARTESIAN_POINT('',(-37.3701815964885,-4.5,21.3777981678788));
#1324=CARTESIAN_POINT('',(-35.7504788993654,-4.5,21.8688327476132));
#1325=CARTESIAN_POINT('',(-34.9303369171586,-4.5,22.080395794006));
#1326=CARTESIAN_POINT('',(-33.2751770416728,-4.5,22.4343743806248));
#1327=CARTESIAN_POINT('',(-32.440157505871,-4.5,22.5767822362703));
#1328=CARTESIAN_POINT('',(-30.7611697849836,-4.5,22.7917102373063));
#1329=CARTESIAN_POINT('',(-29.9172015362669,-4.5,22.8642298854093));
#1330=CARTESIAN_POINT('',(-28.2181957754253,-4.5,22.9396124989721));
#1331=CARTESIAN_POINT('',(-27.3631290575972,-4.5,22.9418102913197));
#1332=CARTESIAN_POINT('',(-25.6556665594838,-4.5,22.8753237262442));
#1333=CARTESIAN_POINT('',(-24.8032707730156,-4.5,22.806639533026));
#1334=CARTESIAN_POINT('',(-23.5313930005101,-4.5,22.6513779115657));
#1335=CARTESIAN_POINT('',(-23.1085598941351,-4.5,22.5909195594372));
#1336=CARTESIAN_POINT('',(-22.2657073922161,-4.5,22.4528004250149));
#1337=CARTESIAN_POINT('',(-21.8456878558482,-4.5,22.375140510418));
#1338=CARTESIAN_POINT('',(-21.00917569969,-4.5,22.2028732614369));
#1339=CARTESIAN_POINT('',(-20.59268285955,-4.5,22.1082669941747));
#1340=CARTESIAN_POINT('',(-19.7637526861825,-4.5,21.9023821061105));
#1341=CARTESIAN_POINT('',(-19.3513161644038,-4.5,21.7911002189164));
#1342=CARTESIAN_POINT('',(-18.5204902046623,-4.5,21.5491075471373));
#1343=CARTESIAN_POINT('',(-18.1022264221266,-4.5,21.417965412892));
#1344=CARTESIAN_POINT('',(-17.2713184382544,-4.5,21.1389427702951));
#1345=CARTESIAN_POINT('',(-16.8586743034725,-4.5,20.9910620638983));
#1346=CARTESIAN_POINT('',(-16.0395222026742,-4.5,20.6790464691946));
#1347=CARTESIAN_POINT('',(-15.6330150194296,-4.5,20.5149095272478));
#1348=CARTESIAN_POINT('',(-14.8267225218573,-4.5,20.1709913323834));
#1349=CARTESIAN_POINT('',(-14.4269365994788,-4.5,19.9912115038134));
#1350=CARTESIAN_POINT('',(-13.6347045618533,-4.5,19.6167786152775));
#1351=CARTESIAN_POINT('',(-13.2422540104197,-4.5,19.4221349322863));
#1352=CARTESIAN_POINT('',(-12.464823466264,-4.5,19.018696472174));
#1353=CARTESIAN_POINT('',(-12.0798417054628,-4.5,18.8099050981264));
#1354=CARTESIAN_POINT('',(-11.3174013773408,-4.5,18.3790390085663));
#1355=CARTESIAN_POINT('',(-10.9399427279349,-4.5,18.1569644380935));
#1356=CARTESIAN_POINT('',(-10.1924778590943,-4.5,17.7006091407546));
#1357=CARTESIAN_POINT('',(-9.82247184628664,-4.5,17.4663280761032));
#1358=CARTESIAN_POINT('',(-9.08559987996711,-4.5,16.9843000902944));
#1359=CARTESIAN_POINT('',(-8.71881175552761,-4.5,16.7364344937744));
#1360=CARTESIAN_POINT('',(-7.99179201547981,-4.5,16.231395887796));
#1361=CARTESIAN_POINT('',(-7.63155957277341,-4.5,15.9742240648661));
#1362=CARTESIAN_POINT('',(-7.09481971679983,-4.5,15.5831540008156));
#1363=CARTESIAN_POINT('',(-6.91641530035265,-4.5,15.4518416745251));
#1364=CARTESIAN_POINT('',(-6.5605876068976,-4.5,15.1878936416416));
#1365=CARTESIAN_POINT('',(-6.38316433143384,-4.5,15.0552579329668));
#1366=CARTESIAN_POINT('',(-6.02896541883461,-4.5,14.7891582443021));
#1367=CARTESIAN_POINT('',(-5.85218972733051,-4.5,14.6556943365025));
#1368=CARTESIAN_POINT('',(-5.49880469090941,-4.5,14.3885487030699));
#1369=CARTESIAN_POINT('',(-5.32219534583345,-4.5,14.2548669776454));
#1370=CARTESIAN_POINT('',(-4.90867410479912,-4.5,13.9428793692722));
#1371=CARTESIAN_POINT('',(-4.67159483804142,-4.5,13.7647925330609));
#1372=CARTESIAN_POINT('',(-4.31385366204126,-4.5,13.5003918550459));
#1373=CARTESIAN_POINT('',(-4.19422078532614,-4.5,13.4126902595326));
#1374=CARTESIAN_POINT('',(-3.95393433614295,-4.5,13.238698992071));
#1375=CARTESIAN_POINT('',(-3.83328078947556,-4.5,13.1524092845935));
#1376=CARTESIAN_POINT('',(-3.59071246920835,-4.5,12.9819298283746));
#1377=CARTESIAN_POINT('',(-3.46879940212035,-4.5,12.8977376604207));
#1378=CARTESIAN_POINT('',(-3.22312011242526,-4.5,12.7321098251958));
#1379=CARTESIAN_POINT('',(-3.09935403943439,-4.5,12.6506739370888));
#1380=CARTESIAN_POINT('',(-2.84953374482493,-4.5,12.4916033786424));
#1381=CARTESIAN_POINT('',(-2.72348150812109,-4.5,12.4139656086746));
#1382=CARTESIAN_POINT('',(-2.4684216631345,-4.5,12.2637217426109));
#1383=CARTESIAN_POINT('',(-2.33941468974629,-4.5,12.1911145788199));
#1384=CARTESIAN_POINT('',(-2.09611955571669,-4.5,12.0623055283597));
#1385=CARTESIAN_POINT('',(-1.98229720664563,-4.5,12.0052296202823));
#1386=CARTESIAN_POINT('',(-1.75164322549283,-4.5,11.8974097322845));
#1387=CARTESIAN_POINT('',(-1.63481121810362,-4.5,11.8466665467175));
#1388=CARTESIAN_POINT('',(-1.39821969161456,-4.5,11.7532751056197));
#1389=CARTESIAN_POINT('',(-1.27846728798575,-4.5,11.7106090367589));
#1390=CARTESIAN_POINT('',(-1.03591448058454,-4.5,11.6351075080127));
#1391=CARTESIAN_POINT('',(-0.913115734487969,-4.5,11.6022668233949));
#1392=CARTESIAN_POINT('',(-0.687245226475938,-4.5,11.5530866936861));
#1393=CARTESIAN_POINT('',(-0.58459007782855,-4.5,11.5348432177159));
#1394=CARTESIAN_POINT('',(-0.378107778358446,-4.5,11.5070275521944));
#1395=CARTESIAN_POINT('',(-0.274280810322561,-4.5,11.4974540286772));
#1396=CARTESIAN_POINT('',(-0.0663499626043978,-4.5,11.4874736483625));
#1397=CARTESIAN_POINT('',(0.0377531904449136,-4.5,11.4870518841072));
#1398=CARTESIAN_POINT('',(0.245597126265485,-4.5,11.495355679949));
#1399=CARTESIAN_POINT('',(0.349337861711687,-4.5,11.5040823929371));
#1400=CARTESIAN_POINT('',(0.57874810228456,-4.5,11.5331714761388));
#1401=CARTESIAN_POINT('',(0.704144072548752,-4.5,11.5556961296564));
#1402=CARTESIAN_POINT('',(0.952319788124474,-4.5,11.6122767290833));
#1403=CARTESIAN_POINT('',(1.07509801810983,-4.5,11.6463391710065));
#1404=CARTESIAN_POINT('',(1.31811581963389,-4.5,11.7242962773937));
#1405=CARTESIAN_POINT('',(1.43833986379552,-4.5,11.7682386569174));
#1406=CARTESIAN_POINT('',(1.67553516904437,-4.5,11.8639761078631));
#1407=CARTESIAN_POINT('',(1.79250732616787,-4.5,11.9157689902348));
#1408=CARTESIAN_POINT('',(2.11305008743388,-4.5,12.0681209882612));
#1409=CARTESIAN_POINT('',(2.31343205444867,-4.5,12.1753505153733));
#1410=CARTESIAN_POINT('',(2.70700145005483,-4.5,12.4023734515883));
#1411=CARTESIAN_POINT('',(2.90018140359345,-4.5,12.5221794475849));
#1412=CARTESIAN_POINT('',(3.28196897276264,-4.5,12.7701259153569));
#1413=CARTESIAN_POINT('',(3.47055948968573,-4.5,12.8982924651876));
#1414=CARTESIAN_POINT('',(3.84419851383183,-4.5,13.1594802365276));
#1415=CARTESIAN_POINT('',(4.0292484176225,-4.5,13.2924994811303));
#1416=CARTESIAN_POINT('',(4.398547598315,-4.5,13.5623066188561));
#1417=CARTESIAN_POINT('',(4.58278233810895,-4.5,13.6991142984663));
#1418=CARTESIAN_POINT('',(4.95022227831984,-4.5,13.9741278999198));
#1419=CARTESIAN_POINT('',(5.13342739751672,-4.5,14.1123339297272));
#1420=CARTESIAN_POINT('',(5.49926330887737,-4.5,14.3887999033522));
#1421=CARTESIAN_POINT('',(5.68189453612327,-4.5,14.5270592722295));
#1422=CARTESIAN_POINT('',(6.04752641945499,-4.5,14.8030891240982));
#1423=CARTESIAN_POINT('',(6.23052707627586,-4.5,14.9408596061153));
#1424=CARTESIAN_POINT('',(6.76546252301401,-4.5,15.3410030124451));
#1425=CARTESIAN_POINT('',(7.11853334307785,-4.5,15.6018686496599));
#1426=CARTESIAN_POINT('',(7.83000188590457,-4.5,16.116261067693));
#1427=CARTESIAN_POINT('',(8.18839955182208,-4.5,16.3697879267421));
#1428=CARTESIAN_POINT('',(8.91193225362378,-4.5,16.867438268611));
#1429=CARTESIAN_POINT('',(9.27707034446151,-4.5,17.1115573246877));
#1430=CARTESIAN_POINT('',(10.0145830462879,-4.5,17.5886036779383));
#1431=CARTESIAN_POINT('',(10.3869573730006,-4.5,17.8215314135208));
#1432=CARTESIAN_POINT('',(11.1379806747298,-4.5,18.2741492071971));
#1433=CARTESIAN_POINT('',(11.5166044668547,-4.5,18.4938809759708));
#1434=CARTESIAN_POINT('',(12.2813511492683,-4.5,18.919899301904));
#1435=CARTESIAN_POINT('',(12.6674740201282,-4.5,19.1261858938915));
#1436=CARTESIAN_POINT('',(13.4470663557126,-4.5,19.52444544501));
#1437=CARTESIAN_POINT('',(13.8405361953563,-4.5,19.7164176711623));
#1438=CARTESIAN_POINT('',(14.6345106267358,-4.5,20.0852979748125));
#1439=CARTESIAN_POINT('',(15.0350156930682,-4.5,20.2622050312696));
#1440=CARTESIAN_POINT('',(15.4388208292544,-4.5,20.4312501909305));
#1441=B_SPLINE_CURVE_WITH_KNOTS('',3,(#1051,#1052,#1053,#1054,#1055,#1056,#1057,#1058,#1059,
#1060,#1061,#1062,#1063,#1064,#1065,#1066,#1067,#1068,#1069,#1070,#1071,#1072,#1073,#1074,#1075,
#1076,#1077,#1078,#1079,#1080,#1081,#1082,#1083,#1084,#1085,#1086,#1087,#1088,#1089,#1090,#1091,
#1092,#1093,#1094,#1095,#1096,#1097,#1098,#1099,#1100,#1101,#1102,#1103,#1104,#1105,#1106,#1107,
#1108,#1109,#1110,#1111,#1112,#1113,#1114,#1115,#1116,#1117,#1118,#1119,#1120,#1121,#1122,#1123,
#1124,#1125,#1126,#1127,#1128,#1129,#1130,#1131,#1132,#1133,#1134,#1135,#1136,#1137,#1138,#1139,
#1140,#1141,#1142,#1143,#1144,#1145,#1146,#1147,#1148,#1149,#1150,#1151,#1152,#1153,#1154,#1155,
#1156,#1157,#1158,#1159,#1160,#1161,#1162,#1163,#1164,#1165,#1166,#1167,#1168,#1169,#1170,#1171,
#1172,#1173,#1174,#1175,#1176,#1177,#1178,#1179,#1180,#1181,#1182,#1183,#1184,#1185,#1186,#1187,
#1188,#1189,#1190,#1191,#1192,#1193,#1194,#1195,#1196,#1197,#1198,#1199,#1200,#1201,#1202,#1203,
#1204,#1205,#1206,#1207,#1208,#1209,#1210,#1211,#1212,#1213,#1214,#1215,#1216,#1217,#1218,#1219,
#1220,#1221,#1222,#1223,#1224,#1225,#1226,#1227,#1228,#1229,#1230,#1231,#1232,#1233,#1234,#1235,
#1236,#1237,#1238,#1239,#1240,#1241,#1242,#1243,#1244,#1245,#1246,#1247,#1248,#1249,#1250,#1251,
#1252,#1253,#1254,#1255,#1256,#1257,#1258,#1259,#1260,#1261,#1262,#1263,#1264,#1265,#1266,#1267,
#1268,#1269,#1270,#1271,#1272,#1273,#1274,#1275,#1276,#1277,#1278,#1279,#1280,#1281,#1282,#1283,
#1284,#1285,#1286,#1287,#1288,#1289,#1290,#1291,#1292,#1293,#1294,#1295,#1296,#1297,#1298,#1299,
#1300,#1301,#1302,#1303,#1304,#1305,#1306,#1307,#1308,#1309,#1310,#1311,#1312,#1313,#1314,#1315,
#1316,#1317,#1318,#1319,#1320,#1321,#1322,#1323,#1324,#1325,#1326,#1327,#1328,#1329,#1330,#1331,
#1332,#1333,#1334,#1335,#1336,#1337,#1338,#1339,#1340,#1341,#1342,#1343,#1344,#1345,#1346,#1347,
#1348,#1349,#1350,#1351,#1352,#1353,#1354,#1355,#1356,#1357,#1358,#1359,#1360,#1361,#1362,#1363,
#1364,#1365,#1366,#1367,#1368,#1369,#1370,#1371,#1372,#1373,#1374,#1375,#1376,#1377,#1378,#1379,
#1380,#1381,#1382,#1383,#1384,#1385,#1386,#1387,#1388,#1389,#1390,#1391,#1392,#1393,#1394,#1395,
#1396,#1397,#1398,#1399,#1400,#1401,#1402,#1403,#1404,#1405,#1406,#1407,#1408,#1409,#1410,#1411,
#1412,#1413,#1414,#1415,#1416,#1417,#1418,#1419,#1420,#1421,#1422,#1423,#1424,#1425,#1426,#1427,
#1428,#1429,#1430,#1431,#1432,#1433,#1434,#1435,#1436,#1437,#1438,#1439,#1440),.UNSPECIFIED.,
.T.,.F.,(4,2,2,2,2,2,2,2,2,2,2,2,2,2,2,2,2,2,2,2,2,2,2,2,2,2,2,2,2,2,2,2,2,2,2,2,2,2,2,2,2,2,2,
2,2,2,2,2,2,2,2,2,2,2,2,2,2,2,2,2,2,2,2,2,2,2,2,2,2,2,2,2,2,2,2,2,2,2,2,2,2,2,2,2,2,2,2,2,2,2,2,
2,2,2,2,2,2,2,2,2,2,2,2,2,2,2,2,2,2,2,2,2,2,2,2,2,2,2,2,2,2,2,2,2,2,2,2,2,2,2,2,2,2,2,2,2,2,2,2,
2,2,2,2,2,2,2,2,2,2,2,2,2,2,2,2,2,2,2,2,2,2,2,2,2,2,2,2,2,2,2,2,2,2,2,2,2,2,2,2,2,2,2,2,2,2,2,2,
2,2,2,2,2,2,2,4),(0.,1.35704731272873,2.714206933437,5.42786400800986,8.14422849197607,
10.8606130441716,13.5601869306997,16.2597656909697,18.9591484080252,21.6584397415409,
24.2372240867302,26.8159253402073,29.3941636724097,31.9723976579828,34.5160692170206,
37.0597130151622,39.603384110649,42.1470525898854,44.6772511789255,47.2074392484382,
49.7375726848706,52.267704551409,54.7919476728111,57.3161862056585,59.840417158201,
62.364647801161,64.88673624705,67.4088226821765,69.9309084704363,72.4529952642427,
74.9756267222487,77.4982576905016,80.0208593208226,82.5434636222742,85.0694600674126,
87.5954571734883,90.1215846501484,92.6477183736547,95.1821827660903,97.7166481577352,
100.25062252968,102.784610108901,105.336431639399,107.88824952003,109.165248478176,
110.442175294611,111.719014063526,112.996131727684,115.598997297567,118.202030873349,
119.501050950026,120.799750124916,122.098534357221,123.397381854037,124.510975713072,
125.624581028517,126.73793945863,127.85130529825,128.967221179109,130.083174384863,
131.199120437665,131.757086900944,132.315052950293,132.702322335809,133.089593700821,
133.864380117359,134.251208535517,134.638011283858,135.024596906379,135.411130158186,
135.786611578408,136.162125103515,136.53702262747,136.91173305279,137.223943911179,
137.536111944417,137.847803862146,138.159510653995,138.469779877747,138.780081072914,
139.091053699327,139.40191165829,140.100140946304,140.799496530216,141.502359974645,
142.204786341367,142.917598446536,143.630494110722,144.341384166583,145.052273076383,
145.956073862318,146.8598711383,147.7636477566,148.667429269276,150.476097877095,
152.284826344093,154.079688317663,155.874577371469,157.669475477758,159.464222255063,
162.084383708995,164.703770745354,167.326947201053,169.95035310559,172.57558898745,
175.200778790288,177.82528765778,180.449764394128,183.013700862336,185.57759454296,
188.141406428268,190.705210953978,193.243693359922,195.782156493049,198.320572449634,
200.858985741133,203.38688715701,205.914780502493,208.442645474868,210.970509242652,
213.493804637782,216.017096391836,218.540382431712,221.063668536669,223.585653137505,
226.107636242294,228.629605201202,231.151575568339,233.674843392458,236.19811110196,
238.721416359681,241.244725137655,243.772615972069,246.300507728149,248.828288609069,
251.356076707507,253.894081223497,256.43208700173,258.970374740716,261.508680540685,
264.070989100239,266.633291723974,267.914401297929,269.195446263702,270.476410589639,
271.757626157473,273.072287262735,274.386963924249,275.701806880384,277.016530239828,
278.330430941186,279.644016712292,280.957588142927,282.271195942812,283.599080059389,
284.926795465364,285.591350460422,286.255906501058,286.920405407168,287.584903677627,
288.474432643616,288.919433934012,289.364424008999,289.808874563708,290.253289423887,
290.697335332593,291.141286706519,291.523128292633,291.905017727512,292.286054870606,
292.666889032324,292.979347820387,293.291758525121,293.603660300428,293.915601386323,
294.297165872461,294.678945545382,295.062610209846,295.446168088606,296.127169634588,
296.808859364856,297.492787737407,298.176440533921,298.864851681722,299.553316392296,
300.240504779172,300.927694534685,302.244597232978,303.561485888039,304.87898680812,
306.196436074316,307.509474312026,308.822509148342,310.135611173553,311.448802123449),.UNSPECIFIED.);
#1442=CARTESIAN_POINT('',(8.87764045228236,-4.5,16.8419191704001));
#1443=VERTEX_POINT('',#1442);
#1444=CARTESIAN_POINT('',(22.55548713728,-4.5,22.5));
#1445=VERTEX_POINT('',#1444);
#1446=EDGE_CURVE('E288',#1443,#1445,#1441,.T.);
#1447=ORIENTED_EDGE('',*,*,#1446,.T.);
#1448=CARTESIAN_POINT('',(11.6425345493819,-4.5,33.0180686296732));
#1449=CARTESIAN_POINT('',(11.8887940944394,-4.5,32.7883606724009));
#1450=CARTESIAN_POINT('',(12.1345901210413,-4.5,32.5581570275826));
#1451=CARTESIAN_POINT('',(12.625380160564,-4.5,32.0968979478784));
#1452=CARTESIAN_POINT('',(12.8703741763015,-4.5,31.8658425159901));
#1453=CARTESIAN_POINT('',(13.6043368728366,-4.5,31.1716115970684));
#1454=CARTESIAN_POINT('',(14.0922926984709,-4.5,30.7073654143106));
#1455=CARTESIAN_POINT('',(15.0661827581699,-4.5,29.7767913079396));
#1456=CARTESIAN_POINT('',(15.5521170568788,-4.5,29.3104634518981));
#1457=CARTESIAN_POINT('',(16.5224491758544,-4.5,28.3762088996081));
#1458=CARTESIAN_POINT('',(17.0068469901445,-4.5,27.9082821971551));
#1459=CARTESIAN_POINT('',(18.4582189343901,-4.5,26.5027042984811));
#1460=CARTESIAN_POINT('',(19.4234130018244,-4.5,25.5632155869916));
#1461=CARTESIAN_POINT('',(21.3507796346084,-4.5,23.6811286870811));
#1462=CARTESIAN_POINT('',(22.3129521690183,-4.5,22.7385304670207));
#1463=CARTESIAN_POINT('',(24.155145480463,-4.5,20.9298325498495));
#1464=CARTESIAN_POINT('',(25.0353323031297,-4.5,20.0639019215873));
#1465=CARTESIAN_POINT('',(26.7944244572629,-4.5,18.3307401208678));
#1466=CARTESIAN_POINT('',(27.6733297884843,-4.5,17.4635089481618));
#1467=CARTESIAN_POINT('',(30.3086128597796,-4.5,14.8603780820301));
#1468=CARTESIAN_POINT('',(32.0635642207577,-4.5,13.1230346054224));
#1469=CARTESIAN_POINT('',(35.5712829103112,-4.5,9.64594205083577));
#1470=CARTESIAN_POINT('',(37.3240501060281,-4.5,7.90619283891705));
#1471=CARTESIAN_POINT('',(39.9520670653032,-4.5,5.29542652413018));
#1472=CARTESIAN_POINT('',(40.8278840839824,-4.5,4.42498033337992));
#1473=CARTESIAN_POINT('',(42.5792011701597,-4.5,2.6837694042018));
#1474=CARTESIAN_POINT('',(43.4547012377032,-4.5,1.81300466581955));
#1475=CARTESIAN_POINT('',(44.3300735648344,-4.5,0.942111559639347));
#1476=B_SPLINE_CURVE_WITH_KNOTS('',3,(#1448,#1449,#1450,#1451,#1452,#1453,#1454,#1455,#1456,
#1457,#1458,#1459,#1460,#1461,#1462,#1463,#1464,#1465,#1466,#1467,#1468,#1469,#1470,#1471,#1472,
#1473,#1474,#1475),.UNSPECIFIED.,.F.,.F.,(4,2,2,2,2,2,2,2,2,2,2,2,2,4),(0.,1.01028789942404,
2.02057224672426,4.04111426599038,6.06159116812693,8.08207591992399,12.1228732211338,
16.1637117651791,19.8679078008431,23.572104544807,30.9804705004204,38.3892670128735,
42.0936681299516,45.7980687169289),.UNSPECIFIED.);
#1477=EDGE_CURVE('E307',#1445,#321,#1476,.T.);
#1478=ORIENTED_EDGE('',*,*,#1477,.T.);
#1479=ORIENTED_EDGE('',*,*,#337,.F.);
#1480=DIRECTION('',(-0.707106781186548,0.,0.707106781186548));
#1481=VECTOR('',#1480,1.);
#1482=CARTESIAN_POINT('',(35.5,-4.5,10.));
#1483=LINE('',#1482,#1481);
#1484=EDGE_CURVE('E395',#361,#329,#1483,.T.);
#1485=ORIENTED_EDGE('',*,*,#1484,.F.);
#1486=ORIENTED_EDGE('',*,*,#362,.F.);
#1487=ORIENTED_EDGE('',*,*,#287,.T.);
#1488=ORIENTED_EDGE('',*,*,#418,.T.);
#1489=DIRECTION('',(0.,0.,1.));
#1490=VECTOR('',#1489,1.);
#1491=CARTESIAN_POINT('',(8.87764045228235,-4.5,0.));
#1492=LINE('',#1491,#1490);
#1493=EDGE_CURVE('E453',#1443,#411,#1492,.T.);
#1494=ORIENTED_EDGE('',*,*,#1493,.F.);
#1495=EDGE_LOOP('',(#1447,#1478,#1479,#1485,#1486,#1487,#1488,#1494));
#1496=FACE_BOUND('',#1495,.T.);
#1497=ADVANCED_FACE('F163',(#1496),#1050,.F.);
#1498=CARTESIAN_POINT('',(8.87764045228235,-10.5,0.));
#1499=DIRECTION('',(0.,0.,1.));
#1500=DIRECTION('',(0.,-1.,0.));
#1501=AXIS2_PLACEMENT_3D('',#1498,#1499,#1500);
#1502=CYLINDRICAL_SURFACE('',#1501,6.);
#1503=CARTESIAN_POINT('',(5.00376098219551,-5.91818181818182,13.6426560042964));
#1504=CARTESIAN_POINT('',(5.0059161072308,-5.91635969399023,13.6453140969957));
#1505=CARTESIAN_POINT('',(5.00807252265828,-5.91453907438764,13.6479722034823));
#1506=CARTESIAN_POINT('',(5.15166899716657,-5.79347607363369,13.8248709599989));
#1507=CARTESIAN_POINT('',(5.29866177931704,-5.68069412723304,13.9991457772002));
#1508=CARTESIAN_POINT('',(5.60512104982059,-5.46755607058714,14.3446312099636));
#1509=CARTESIAN_POINT('',(5.76459853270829,-5.3672111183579,14.5158389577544));
#1510=CARTESIAN_POINT('',(6.09738136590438,-5.17960738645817,14.8511218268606));
#1511=CARTESIAN_POINT('',(6.27065600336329,-5.09232072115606,15.0152116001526));
#1512=CARTESIAN_POINT('',(6.6332433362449,-4.93206553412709,15.332036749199));
#1513=CARTESIAN_POINT('',(6.82252989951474,-4.85907430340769,15.4847898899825));
#1514=CARTESIAN_POINT('',(7.09690043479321,-4.76978611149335,15.6842480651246));
#1515=CARTESIAN_POINT('',(7.17434337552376,-4.74626344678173,15.7383131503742));
#1516=CARTESIAN_POINT('',(7.33200550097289,-4.70192108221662,15.8435010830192));
#1517=CARTESIAN_POINT('',(7.41222599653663,-4.68110268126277,15.8946225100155));
#1518=CARTESIAN_POINT('',(7.49386505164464,-4.66174977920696,15.9440475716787));
#1519=B_SPLINE_CURVE_WITH_KNOTS('',3,(#1503,#1504,#1505,#1506,#1507,#1508,#1509,#1510,#1511,
#1512,#1513,#1514,#1515,#1516,#1517,#1518),.UNSPECIFIED.,.F.,.F.,(4,2,2,2,2,2,2,4),(0.,
0.0116306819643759,0.774027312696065,1.53710306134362,2.29852527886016,3.05872795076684,
3.35062276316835,3.64265726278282),.UNSPECIFIED.);
#1520=CARTESIAN_POINT('',(7.49353468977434,-4.66182809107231,15.9438475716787));
#1521=VERTEX_POINT('',#1520);
#1522=EDGE_CURVE('E260',#450,#1521,#1519,.T.);
#1523=ORIENTED_EDGE('',*,*,#1522,.T.);
#1524=CARTESIAN_POINT('',(7.49320434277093,-4.66190641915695,15.9436475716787));
#1525=CARTESIAN_POINT('',(7.60943905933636,-4.63435875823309,16.0140509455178));
#1526=CARTESIAN_POINT('',(7.72548993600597,-4.61048878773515,16.0861329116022));
#1527=CARTESIAN_POINT('',(7.95693991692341,-4.56989665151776,16.2326288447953));
#1528=CARTESIAN_POINT('',(8.07233993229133,-4.55315590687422,16.3070362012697));
#1529=CARTESIAN_POINT('',(8.30280331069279,-4.52647413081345,16.457529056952));
#1530=CARTESIAN_POINT('',(8.41786670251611,-4.51653249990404,16.5336144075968));
#1531=CARTESIAN_POINT('',(8.64795886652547,-4.50329006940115,16.687069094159));
#1532=CARTESIAN_POINT('',(8.76298675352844,-4.50000678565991,16.7644412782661));
#1533=CARTESIAN_POINT('',(8.87784045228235,-4.50000000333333,16.8420543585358));
#1534=B_SPLINE_CURVE_WITH_KNOTS('',3,(#1524,#1525,#1526,#1527,#1528,#1529,#1530,#1531,#1532,
#1533),.UNSPECIFIED.,.F.,.F.,(4,2,2,2,4),(0.,0.415867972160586,0.830645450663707,
1.24538635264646,1.66121688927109),.UNSPECIFIED.);
#1535=EDGE_CURVE('E281',#1521,#1443,#1534,.T.);
#1536=ORIENTED_EDGE('',*,*,#1535,.T.);
#1537=ORIENTED_EDGE('',*,*,#1493,.T.);
#1538=ORIENTED_EDGE('',*,*,#412,.T.);
#1539=CARTESIAN_POINT('',(5.00376098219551,-5.91818181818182,26.7442638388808));
#1540=CARTESIAN_POINT('',(5.0185510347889,-5.90567678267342,26.7640009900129));
#1541=CARTESIAN_POINT('',(5.03308032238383,-5.89351543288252,26.784152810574));
#1542=CARTESIAN_POINT('',(5.06152881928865,-5.86992091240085,26.8252223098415));
#1543=CARTESIAN_POINT('',(5.07544919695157,-5.85848632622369,26.8461383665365));
#1544=CARTESIAN_POINT('',(5.10265156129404,-5.83633549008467,26.8887528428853));
#1545=CARTESIAN_POINT('',(5.11593353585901,-5.82561925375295,26.910451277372));
#1546=CARTESIAN_POINT('',(5.14182657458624,-5.80489933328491,26.9546446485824));
#1547=CARTESIAN_POINT('',(5.1544362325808,-5.79489712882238,26.9771411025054));
#1548=CARTESIAN_POINT('',(5.16666666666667,-5.78527057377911,27.));
#1549=B_SPLINE_CURVE_WITH_KNOTS('',3,(#1539,#1540,#1541,#1542,#1543,#1544,#1545,#1546,#1547,
#1548),.UNSPECIFIED.,.F.,.F.,(4,2,2,2,4),(0.,0.0829534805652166,0.165740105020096,
0.248528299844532,0.331483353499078),.UNSPECIFIED.);
#1550=EDGE_CURVE('E203',#458,#402,#1549,.T.);
#1551=ORIENTED_EDGE('',*,*,#1550,.F.);
#1552=ORIENTED_EDGE('',*,*,#459,.F.);
#1553=EDGE_LOOP('',(#1523,#1536,#1537,#1538,#1551,#1552));
#1554=FACE_BOUND('',#1553,.T.);
#1555=ADVANCED_FACE('F198',(#1554),#1502,.F.);
#1556=CARTESIAN_POINT('',(7.75,0.,6.));
#1557=DIRECTION('',(0.,0.,1.));
#1558=DIRECTION('',(0.,-1.,0.));
#1559=AXIS2_PLACEMENT_3D('',#1556,#1557,#1558);
#1560=PLANE('',#1559);
#1561=CARTESIAN_POINT('',(0.,0.,6.));
#1562=DIRECTION('',(0.,0.,-1.));
#1563=DIRECTION('',(0.,1.,0.));
#1564=AXIS2_PLACEMENT_3D('',#1561,#1562,#1563);
#1565=CIRCLE('',#1564,6.);
#1566=CARTESIAN_POINT('',(0.,6.,6.));
#1567=VERTEX_POINT('',#1566);
#1568=EDGE_CURVE('E432',#1567,#1567,#1565,.T.);
#1569=ORIENTED_EDGE('',*,*,#1568,.F.);
#1570=EDGE_LOOP('',(#1569));
#1571=FACE_BOUND('',#1570,.T.);
#1572=ORIENTED_EDGE('',*,*,#521,.T.);
#1573=EDGE_LOOP('',(#1572));
#1574=FACE_BOUND('',#1573,.T.);
#1575=ADVANCED_FACE('F482',(#1571,#1574),#1560,.F.);
#1576=CARTESIAN_POINT('',(0.,0.,0.));
#1577=DIRECTION('',(0.,0.,-1.));
#1578=DIRECTION('',(0.,1.,0.));
#1579=AXIS2_PLACEMENT_3D('',#1576,#1577,#1578);
#1580=CYLINDRICAL_SURFACE('',#1579,6.);
#1581=CARTESIAN_POINT('',(0.,0.,0.2));
#1582=DIRECTION('',(0.,0.,-1.));
#1583=DIRECTION('',(0.,1.,0.));
#1584=AXIS2_PLACEMENT_3D('',#1581,#1582,#1583);
#1585=CIRCLE('',#1584,6.);
#1586=CARTESIAN_POINT('',(0.,6.,0.2));
#1587=VERTEX_POINT('',#1586);
#1588=EDGE_CURVE('E435',#1587,#1587,#1585,.T.);
#1589=ORIENTED_EDGE('',*,*,#1588,.F.);
#1590=EDGE_LOOP('',(#1589));
#1591=FACE_BOUND('',#1590,.T.);
#1592=ORIENTED_EDGE('',*,*,#1568,.T.);
#1593=EDGE_LOOP('',(#1592));
#1594=FACE_BOUND('',#1593,.T.);
#1595=ADVANCED_FACE('F484',(#1591,#1594),#1580,.T.);
#1596=CARTESIAN_POINT('',(6.,0.,0.2));
#1597=DIRECTION('',(0.,0.,1.));
#1598=DIRECTION('',(0.,-1.,0.));
#1599=AXIS2_PLACEMENT_3D('',#1596,#1597,#1598);
#1600=PLANE('',#1599);
#1601=CARTESIAN_POINT('',(0.,0.,0.2));
#1602=DIRECTION('',(0.,0.,-1.));
#1603=DIRECTION('',(0.,1.,0.));
#1604=AXIS2_PLACEMENT_3D('',#1601,#1602,#1603);
#1605=CIRCLE('',#1604,4.8);
#1606=CARTESIAN_POINT('',(0.,4.8,0.2));
#1607=VERTEX_POINT('',#1606);
#1608=EDGE_CURVE('E438',#1607,#1607,#1605,.T.);
#1609=ORIENTED_EDGE('',*,*,#1608,.F.);
#1610=EDGE_LOOP('',(#1609));
#1611=FACE_BOUND('',#1610,.T.);
#1612=ORIENTED_EDGE('',*,*,#1588,.T.);
#1613=EDGE_LOOP('',(#1612));
#1614=FACE_BOUND('',#1613,.T.);
#1615=ADVANCED_FACE('F492',(#1611,#1614),#1600,.F.);
#1616=CARTESIAN_POINT('',(0.,0.,0.));
#1617=DIRECTION('',(0.,0.,-1.));
#1618=DIRECTION('',(0.,1.,0.));
#1619=AXIS2_PLACEMENT_3D('',#1616,#1617,#1618);
#1620=CYLINDRICAL_SURFACE('',#1619,4.8);
#1621=ORIENTED_EDGE('',*,*,#59,.F.);
#1622=EDGE_LOOP('',(#1621));
#1623=FACE_BOUND('',#1622,.T.);
#1624=ORIENTED_EDGE('',*,*,#1608,.T.);
#1625=EDGE_LOOP('',(#1624));
#1626=FACE_BOUND('',#1625,.T.);
#1627=ADVANCED_FACE('F324',(#1623,#1626),#1620,.T.);
#1628=EDGE_CURVE('E303',#604,#319,#317,.T.);
#1629=ORIENTED_EDGE('',*,*,#1628,.F.);
#1630=ORIENTED_EDGE('',*,*,#607,.T.);
#1631=EDGE_CURVE('E390',#319,#606,#327,.T.);
#1632=ORIENTED_EDGE('',*,*,#1631,.F.);
#1633=EDGE_LOOP('',(#1629,#1630,#1632));
#1634=FACE_BOUND('',#1633,.T.);
#1635=ADVANCED_FACE('F321',(#1634),#298,.F.);
#1636=CARTESIAN_POINT('',(25.,-9.,20.5));
#1637=DIRECTION('',(-0.707106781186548,0.,-0.707106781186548));
#1638=DIRECTION('',(0.707106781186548,0.,-0.707106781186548));
#1639=AXIS2_PLACEMENT_3D('',#1636,#1637,#1638);
#1640=PLANE('',#1639);
#1641=ORIENTED_EDGE('',*,*,#1041,.T.);
#1642=ORIENTED_EDGE('',*,*,#370,.F.);
#1643=ORIENTED_EDGE('',*,*,#1484,.T.);
#1644=ORIENTED_EDGE('',*,*,#330,.T.);
#1645=ORIENTED_EDGE('',*,*,#1631,.T.);
#1646=EDGE_LOOP('',(#1641,#1642,#1643,#1644,#1645));
#1647=FACE_BOUND('',#1646,.T.);
#1648=ADVANCED_FACE('F196',(#1647),#1640,.T.);
#1649=CARTESIAN_POINT('',(3.4032358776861,-9.,27.943563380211));
#1650=DIRECTION('',(0.,1.,0.));
#1651=DIRECTION('',(-1.,0.,0.));
#1652=AXIS2_PLACEMENT_3D('',#1649,#1650,#1651);
#1653=CYLINDRICAL_SURFACE('',#1652,1.99999999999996);
#1654=ORIENTED_EDGE('',*,*,#504,.T.);
#1655=ORIENTED_EDGE('',*,*,#84,.F.);
#1656=ORIENTED_EDGE('',*,*,#480,.T.);
#1657=ORIENTED_EDGE('',*,*,#1550,.T.);
#1658=ORIENTED_EDGE('',*,*,#403,.T.);
#1659=ORIENTED_EDGE('',*,*,#587,.T.);
#1660=EDGE_LOOP('',(#1654,#1655,#1656,#1657,#1658,#1659));
#1661=FACE_BOUND('',#1660,.T.);
#1662=ADVANCED_FACE('F189',(#1661),#1653,.F.);
#1663=CARTESIAN_POINT('',(29.,-9.,26.));
#1664=DIRECTION('',(0.,1.,0.));
#1665=DIRECTION('',(-1.,0.,0.));
#1666=AXIS2_PLACEMENT_3D('',#1663,#1664,#1665);
#1667=CYLINDRICAL_SURFACE('',#1666,1.);
#1668=ORIENTED_EDGE('',*,*,#275,.T.);
#1669=ORIENTED_EDGE('',*,*,#246,.T.);
#1670=ORIENTED_EDGE('',*,*,#425,.F.);
#1671=EDGE_LOOP('',(#1668,#1669,#1670));
#1672=FACE_BOUND('',#1671,.T.);
#1673=ADVANCED_FACE('F184',(#1672),#1667,.T.);
#1674=CARTESIAN_POINT('',(0.,0.,23.1));
#1675=DIRECTION('',(0.,0.,-1.));
#1676=DIRECTION('',(0.,1.,0.));
#1677=AXIS2_PLACEMENT_3D('',#1674,#1675,#1676);
#1678=TOROIDAL_SURFACE('',#1677,27.4,2.6);
#1679=ORIENTED_EDGE('',*,*,#191,.F.);
#1680=ORIENTED_EDGE('',*,*,#148,.F.);
#1681=ORIENTED_EDGE('',*,*,#353,.F.);
#1682=EDGE_LOOP('',(#1679,#1680,#1681));
#1683=FACE_BOUND('',#1682,.T.);
#1684=ADVANCED_FACE('F132',(#1683),#1678,.T.);
#1685=CARTESIAN_POINT('',(0.,0.,13.6426560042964));
#1686=DIRECTION('',(0.,0.,-1.));
#1687=DIRECTION('',(0.,1.,0.));
#1688=AXIS2_PLACEMENT_3D('',#1685,#1686,#1687);
#1689=TOROIDAL_SURFACE('',#1688,10.75,3.);
#1690=CARTESIAN_POINT('',(0.,0.,15.9438475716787));
#1691=DIRECTION('',(0.,0.,-1.));
#1692=DIRECTION('',(0.,1.,0.));
#1693=AXIS2_PLACEMENT_3D('',#1690,#1691,#1692);
#1694=CIRCLE('',#1693,8.82528771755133);
#1695=EDGE_CURVE('E370',#551,#1521,#1694,.T.);
#1696=ORIENTED_EDGE('',*,*,#1695,.T.);
#1697=ORIENTED_EDGE('',*,*,#1522,.F.);
#1698=ORIENTED_EDGE('',*,*,#451,.F.);
#1699=ORIENTED_EDGE('',*,*,#573,.F.);
#1700=EDGE_LOOP('',(#1696,#1697,#1698,#1699));
#1701=FACE_BOUND('',#1700,.T.);
#1702=ADVANCED_FACE('F274',(#1701),#1689,.F.);
#1703=CARTESIAN_POINT('',(0.,0.,-7.06806810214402));
#1704=DIRECTION('',(0.,0.,-1.));
#1705=DIRECTION('',(0.,1.,0.));
#1706=AXIS2_PLACEMENT_3D('',#1703,#1704,#1705);
#1707=DEGENERATE_TOROIDAL_SURFACE('',#1706,28.072410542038,30.,.T.);
#1708=ORIENTED_EDGE('',*,*,#1031,.F.);
#1709=CARTESIAN_POINT('',(0.,0.,22.5));
#1710=DIRECTION('',(0.,0.,-1.));
#1711=DIRECTION('',(0.,1.,0.));
#1712=AXIS2_PLACEMENT_3D('',#1709,#1710,#1711);
#1713=CIRCLE('',#1712,23.);
#1714=EDGE_CURVE('E29',#639,#319,#1713,.T.);
#1715=ORIENTED_EDGE('',*,*,#1714,.T.);
#1716=EDGE_CURVE('E377',#319,#1445,#1713,.T.);
#1717=ORIENTED_EDGE('',*,*,#1716,.T.);
#1718=ORIENTED_EDGE('',*,*,#1446,.F.);
#1719=ORIENTED_EDGE('',*,*,#1535,.F.);
#1720=ORIENTED_EDGE('',*,*,#1695,.F.);
#1721=ORIENTED_EDGE('',*,*,#552,.F.);
#1722=EDGE_LOOP('',(#1708,#1715,#1717,#1718,#1719,#1720,#1721));
#1723=FACE_BOUND('',#1722,.T.);
#1724=ADVANCED_FACE('F270',(#1723),#1707,.F.);
#1725=CARTESIAN_POINT('',(0.,0.,20.5));
#1726=DIRECTION('',(0.,0.,-1.));
#1727=DIRECTION('',(0.,1.,0.));
#1728=AXIS2_PLACEMENT_3D('',#1725,#1726,#1727);
#1729=CONICAL_SURFACE('',#1728,25.,0.785398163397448);
#1730=ORIENTED_EDGE('',*,*,#1628,.T.);
#1731=ORIENTED_EDGE('',*,*,#1714,.F.);
#1732=ORIENTED_EDGE('',*,*,#640,.F.);
#1733=EDGE_LOOP('',(#1730,#1731,#1732));
#1734=FACE_BOUND('',#1733,.T.);
#1735=ADVANCED_FACE('F273',(#1734),#1729,.F.);
#1736=ORIENTED_EDGE('',*,*,#1716,.F.);
#1737=ORIENTED_EDGE('',*,*,#322,.T.);
#1738=ORIENTED_EDGE('',*,*,#1477,.F.);
#1739=EDGE_LOOP('',(#1736,#1737,#1738));
#1740=FACE_BOUND('',#1739,.T.);
#1741=ADVANCED_FACE('F357',(#1740),#1729,.F.);
#1742=CARTESIAN_POINT('',(0.,0.,29.7));
#1743=DIRECTION('',(0.,0.,-1.));
#1744=DIRECTION('',(0.,1.,0.));
#1745=AXIS2_PLACEMENT_3D('',#1742,#1743,#1744);
#1746=PLANE('',#1745);
#1747=CARTESIAN_POINT('',(0.,0.,29.7));
#1748=DIRECTION('',(0.,0.,-1.));
#1749=DIRECTION('',(0.,1.,0.));
#1750=AXIS2_PLACEMENT_3D('',#1747,#1748,#1749);
#1751=CIRCLE('',#1750,2.69047619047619);
#1752=CARTESIAN_POINT('',(0.,2.69047619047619,29.7));
#1753=VERTEX_POINT('',#1752);
#1754=EDGE_CURVE('E366',#1753,#1753,#1751,.T.);
#1755=ORIENTED_EDGE('',*,*,#1754,.F.);
#1756=EDGE_LOOP('',(#1755));
#1757=FACE_BOUND('',#1756,.T.);
#1758=ADVANCED_FACE('F354',(#1757),#1746,.F.);
#1759=CARTESIAN_POINT('',(0.,0.,28.7));
#1760=DIRECTION('',(0.,0.,-1.));
#1761=DIRECTION('',(0.,1.,0.));
#1762=AXIS2_PLACEMENT_3D('',#1759,#1760,#1761);
#1763=TOROIDAL_SURFACE('',#1762,2.69047619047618,1.);
#1764=ORIENTED_EDGE('',*,*,#1754,.T.);
#1765=EDGE_LOOP('',(#1764));
#1766=FACE_BOUND('',#1765,.T.);
#1767=CARTESIAN_POINT('',(0.,0.,28.7));
#1768=DIRECTION('',(0.,0.,-1.));
#1769=DIRECTION('',(0.,1.,0.));
#1770=AXIS2_PLACEMENT_3D('',#1767,#1768,#1769);
#1771=CIRCLE('',#1770,3.69047619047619);
#1772=CARTESIAN_POINT('',(0.,3.69047619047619,28.7));
#1773=VERTEX_POINT('',#1772);
#1774=EDGE_CURVE('E368',#1773,#1773,#1771,.T.);
#1775=ORIENTED_EDGE('',*,*,#1774,.F.);
#1776=EDGE_LOOP('',(#1775));
#1777=FACE_BOUND('',#1776,.T.);
#1778=ADVANCED_FACE('F351',(#1766,#1777),#1763,.T.);
#1779=CARTESIAN_POINT('',(0.,0.,26.));
#1780=DIRECTION('',(0.,0.,-1.));
#1781=DIRECTION('',(0.,1.,0.));
#1782=AXIS2_PLACEMENT_3D('',#1779,#1780,#1781);
#1783=CYLINDRICAL_SURFACE('',#1782,3.69047619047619);
#1784=ORIENTED_EDGE('',*,*,#95,.T.);
#1785=EDGE_LOOP('',(#1784));
#1786=FACE_BOUND('',#1785,.T.);
#1787=ORIENTED_EDGE('',*,*,#1774,.T.);
#1788=EDGE_LOOP('',(#1787));
#1789=FACE_BOUND('',#1788,.T.);
#1790=ADVANCED_FACE('F347',(#1786,#1789),#1783,.T.);
#1791=CARTESIAN_POINT('',(0.,0.,10.));
#1792=DIRECTION('',(0.,0.,-1.));
#1793=DIRECTION('',(0.,1.,0.));
#1794=AXIS2_PLACEMENT_3D('',#1791,#1792,#1793);
#1795=CYLINDRICAL_SURFACE('',#1794,2.5);
#1796=ORIENTED_EDGE('',*,*,#48,.T.);
#1797=EDGE_LOOP('',(#1796));
#1798=FACE_BOUND('',#1797,.T.);
#1799=ORIENTED_EDGE('',*,*,#31,.F.);
#1800=EDGE_LOOP('',(#1799));
#1801=FACE_BOUND('',#1800,.T.);
#1802=ADVANCED_FACE('F344',(#1798,#1801),#1795,.F.);
#1803=CLOSED_SHELL('',(#35,#63,#99,#293,#341,#380,#436,#525,#592,#1045,#1497,#1555,#1575,#1595,
#1615,#1627,#1635,#1648,#1662,#1673,#1684,#1702,#1724,#1735,#1741,#1758,#1778,#1790,#1802));
#1804=MANIFOLD_SOLID_BREP('B1',#1803);
#1805=ADVANCED_BREP_SHAPE_REPRESENTATION('',(#18,#1804),#14);
#1806=SHAPE_DEFINITION_REPRESENTATION(#9,#1805);
ENDSEC;
END-ISO-10303-21;
